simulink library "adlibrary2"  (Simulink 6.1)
undefined symbols (not defined in the file or in its folder): adlibrary2, ADM, Bit, Black, Box, d2sram_config, DDR, ddr32_config, Generation, II, Inactive, Location, Lower, SDRAM, Simulation, Subsystem, Width, xbsIndex_r3, XPL, XRC, XRM, zbt32_config, zbt64_config
libraries: xbsIndex_r3 x633
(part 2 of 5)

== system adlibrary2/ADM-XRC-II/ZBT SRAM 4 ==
  d : Inport  Port=1  LatchInput=off
  a : Inport  Port=2  LatchInput=off
  w : Inport  Port=3  LatchInput=off
  r : Inport  Port=4  LatchInput=off
  be : Inport  Port=5  LatchInput=off
  adlocb_in : Inport  Port=6  LatchInput=off
  Constant : xbsIndex_r3/Constant  const=0  equ=P=C  arith_type=Unsigned  n_bits=34  bin_pt=0  opselect=C  inp2=PCIN>>17  opr=+  inp1=P  carry=CIN  iostate=0  explicit_period=on  period=1  dbl_ovrd=off
  Convert : xbsIndex_r3/Convert  arith_type=Unsigned  n_bits=34  bin_pt=0  quantization=Truncate  overflow=Wrap  latency=0  explicit_period=on  period=1  dbl_ovrd=off  show_param=off  inserted_by_tool=off  pipeline=off
  Simulation Multiplexer : xbsIndex_r3/Simulation Multiplexer  sim_sel=1  hw_sel=2
  Simulation Multiplexer1 : xbsIndex_r3/Simulation Multiplexer  sim_sel=1  hw_sel=2
  Simulation Multiplexer2 : xbsIndex_r3/Simulation Multiplexer  sim_sel=1  hw_sel=2
  ZBT SRAM 32Bit Generation : Subsystem
  ZBT SRAM 32Bit Simulation : Subsystem
  q : Outport
  qv : Outport  Port=2
  adlocb_out : Outport  Port=3
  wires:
  Constant/1 -> Simulation Multiplexer2/1
  adlocb_in/1 -> ZBT SRAM 32Bit Generation/6(adlocb_in)
  ZBT SRAM 32Bit Generation/3(adlocb_out) -> Convert/1
  Simulation Multiplexer2/1 -> adlocb_out/1
  be/1 -> ZBT SRAM 32Bit Generation/5(be), ZBT SRAM 32Bit Simulation/5(be)
  Simulation Multiplexer/1 -> q/1
  Simulation Multiplexer1/1 -> qv/1
  ZBT SRAM 32Bit Generation/2(qv) -> Simulation Multiplexer1/2
  ZBT SRAM 32Bit Generation/1(q) -> Simulation Multiplexer/2
  ZBT SRAM 32Bit Simulation/1(q) -> Simulation Multiplexer/1
  ZBT SRAM 32Bit Simulation/2(qv) -> Simulation Multiplexer1/1
  d/1 -> ZBT SRAM 32Bit Simulation/1(d), ZBT SRAM 32Bit Generation/1(d)
  a/1 -> ZBT SRAM 32Bit Simulation/2(a), ZBT SRAM 32Bit Generation/2(a)
  w/1 -> ZBT SRAM 32Bit Simulation/3(w), ZBT SRAM 32Bit Generation/3(w)
  r/1 -> ZBT SRAM 32Bit Simulation/4(r), ZBT SRAM 32Bit Generation/4(r)
  Convert/1 -> Simulation Multiplexer2/2

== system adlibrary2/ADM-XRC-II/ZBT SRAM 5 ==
  d : Inport  Port=1  LatchInput=off
  a : Inport  Port=2  LatchInput=off
  w : Inport  Port=3  LatchInput=off
  r : Inport  Port=4  LatchInput=off
  be : Inport  Port=5  LatchInput=off
  adlocb_in : Inport  Port=6  LatchInput=off
  Constant : xbsIndex_r3/Constant  const=0  equ=P=C  arith_type=Unsigned  n_bits=34  bin_pt=0  opselect=C  inp2=PCIN>>17  opr=+  inp1=P  carry=CIN  iostate=0  explicit_period=on  period=1  dbl_ovrd=off
  Convert : xbsIndex_r3/Convert  arith_type=Unsigned  n_bits=34  bin_pt=0  quantization=Truncate  overflow=Wrap  latency=0  explicit_period=on  period=1  dbl_ovrd=off  show_param=off  inserted_by_tool=off  pipeline=off
  Simulation Multiplexer : xbsIndex_r3/Simulation Multiplexer  sim_sel=1  hw_sel=2
  Simulation Multiplexer1 : xbsIndex_r3/Simulation Multiplexer  sim_sel=1  hw_sel=2
  Simulation Multiplexer2 : xbsIndex_r3/Simulation Multiplexer  sim_sel=1  hw_sel=2
  ZBT SRAM 32Bit Generation : Subsystem
  ZBT SRAM 32Bit Simulation : Subsystem
  q : Outport
  qv : Outport  Port=2
  adlocb_out : Outport  Port=3
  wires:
  r/1 -> ZBT SRAM 32Bit Generation/4(r), ZBT SRAM 32Bit Simulation/4(r)
  w/1 -> ZBT SRAM 32Bit Generation/3(w), ZBT SRAM 32Bit Simulation/3(w)
  a/1 -> ZBT SRAM 32Bit Generation/2(a), ZBT SRAM 32Bit Simulation/2(a)
  d/1 -> ZBT SRAM 32Bit Generation/1(d), ZBT SRAM 32Bit Simulation/1(d)
  ZBT SRAM 32Bit Simulation/2(qv) -> Simulation Multiplexer1/1
  ZBT SRAM 32Bit Simulation/1(q) -> Simulation Multiplexer/1
  ZBT SRAM 32Bit Generation/1(q) -> Simulation Multiplexer/2
  ZBT SRAM 32Bit Generation/2(qv) -> Simulation Multiplexer1/2
  Simulation Multiplexer1/1 -> qv/1
  Simulation Multiplexer/1 -> q/1
  be/1 -> ZBT SRAM 32Bit Simulation/5(be), ZBT SRAM 32Bit Generation/5(be)
  Simulation Multiplexer2/1 -> adlocb_out/1
  ZBT SRAM 32Bit Generation/3(adlocb_out) -> Convert/1
  adlocb_in/1 -> ZBT SRAM 32Bit Generation/6(adlocb_in)
  Constant/1 -> Simulation Multiplexer2/1
  Convert/1 -> Simulation Multiplexer2/2

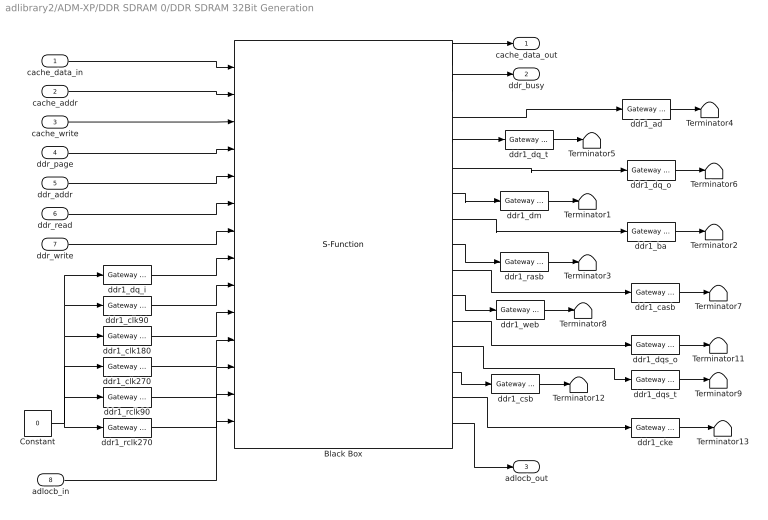
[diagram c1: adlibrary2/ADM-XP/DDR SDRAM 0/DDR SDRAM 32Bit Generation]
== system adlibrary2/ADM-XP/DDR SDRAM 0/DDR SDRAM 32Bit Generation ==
  cache_data_in : Inport  Port=1  LatchInput=off
  cache_addr : Inport  Port=2  LatchInput=off
  cache_write : Inport  Port=3  LatchInput=off
  ddr_page : Inport  Port=4  LatchInput=off
  ddr_addr : Inport  Port=5  LatchInput=off
  ddr_read : Inport  Port=6  LatchInput=off
  ddr_write : Inport  Port=7  LatchInput=off
  adlocb_in : Inport  Port=8  LatchInput=off
  Black Box : S-Function  AncestorBlock=xbsIndex_r3/Black Box  FunctionName=xlblackbox2  Parameters=sfcn_mwsv__  mask(Xilinx Blackbox Block){init_code=ddr32_config, sim_method=Inactive, engine_block=, show_param=on, xl_area=[375, 550, 2, 337, 9, 0, 0], xl_use_area=on, adlocb_devid=4, ddr_size=64}
      mask prompts: init_code "Block Configuration M-Function"; sim_method "Simulation Mode"; engine_block "HDL Co-Simulator To Use  (specify helper block by name)"; show_param "---------------------- Show Implementation Parameters -----------------------------------------------------------------------------------"; xl_area "FPGA Area [Slices, FFs, BRAMs, LUTs, IOBs, Emb. Mults, TBUFs]"; xl_use_area "Use Area Above For Estimation"; adlocb_devid "ADLOCB DEV ID"; ddr_size "DDR BANK SIZE(MB)"
      mask help: Incorporates black box HDL and simulation model into a System Generator design. You must supply a Black Box with certain information about the HDL component you would like to bring into System Generator. This information is provided through a Matlab function. When "Simulation Mode" is set to "Inactive," you will typically want to provide a separate simulation model by using a Simulation Multiplexer. When "Simulation Mode" is set to "Use HDL Co-Simulation", you must include a ModelSim block in the design.
      mask init:
      | [designRoot, family, part, speed, package, simulinkPeriod, sysclkPeriod, dbl_ovrd, trimVbit] = xlSysgenSettings(gcb,0,0);
      | 
      | [bg,fg] = xlcmap('XBlock');
      | iPos = get_param(gcb,'Position');
      | iWidth=iPos(3)-iPos(1); iHeight=iPos(4)-iPos(2);
      | iCx=iWidth/2;
      | iCy=iHeight/2;
      | [logoX, logoY] = xlogo(iPos);
      | zstr='z'; zpstr='-1';
      | zstrx = iCx-3; if (zstrx<16) zstr='';zpstr=''; end
      | zstry = iCy;
      | 
      | precision0 = 1;
      | latency = 0;
      | dblOvrd = 0;
      | 
      | mdlPath = xlGetMdlDir(bdroot);
      | 
      | refBlk = get_param(gcb,'referenceBlock');
      | if (isempty(refBlk) | strncmp(refBlk,'xbsIndex',8))
      | 	srcPath = mdlPath;
      | else
      | 	srcPath = xlPathToReference;
      | 	if (isempty(srcPath))
      | 		srcPath = mdlPath;
      | 	end
      | end
      | 
      | if (sim_method==2)
      | 	validEngineBlock = 0;
      | 	try
      | 	  engineBlock = xlBlockNameRelPath(get_param(gcb,'Parent'),engine_block);
      | 	catch
      | 	  engineBlock = '//';
      | 	end
      | 	try 
      | 	  engineWorkDir = get_param(engineBlock,'dir');
      | 	  validEngineBlock = 1;
      | 	catch
      | 	end
      | end
      | 
      | % just pass everything to s-function
      | sfcn_mwsv__ = get_param(gcb, 'MaskWSVariables');
      | 
      | plabel = xlbbPortLabelStruct(gcb,init_code,mdlPath);
  Constant : Constant  Value=0
  Terminator{1..9,11..13} (12 alike) : Terminator
  ddr1_ad : xbsIndex_r3/Gateway Out  output_type=Double  nbits=8  bin_pt=6  arith_type=Boolean  quantization=Truncate  overflow=Wrap  hdl_port=on  timing_constraint=None  locs_specified=off  LOCs={}  needs_fixed_name=off  show_param=off
  ddr1_ba : xbsIndex_r3/Gateway Out  output_type=Double  nbits=8  bin_pt=6  arith_type=Boolean  quantization=Truncate  overflow=Wrap  hdl_port=on  timing_constraint=None  locs_specified=off  LOCs={}  needs_fixed_name=off  show_param=off
  ddr1_casb : xbsIndex_r3/Gateway Out  output_type=Double  nbits=8  bin_pt=6  arith_type=Boolean  quantization=Truncate  overflow=Wrap  hdl_port=on  timing_constraint=None  locs_specified=off  LOCs={}  needs_fixed_name=off  show_param=off
  ddr1_cke : xbsIndex_r3/Gateway Out  output_type=Double  nbits=8  bin_pt=6  arith_type=Boolean  quantization=Truncate  overflow=Wrap  hdl_port=on  timing_constraint=None  locs_specified=off  LOCs={}  needs_fixed_name=off  show_param=off
  ddr1_clk180 : xbsIndex_r3/Gateway In  arith_type=Boolean  n_bits=64  bin_pt=0  quantization=Truncate  overflow=Wrap  period=1  timing_constraint=None  locs_specified=off  LOCs={}  needs_fixed_name=off  dbl_ovrd=off  show_param=off
  ddr1_clk270 : xbsIndex_r3/Gateway In  arith_type=Boolean  n_bits=64  bin_pt=0  quantization=Truncate  overflow=Wrap  period=1  timing_constraint=None  locs_specified=off  LOCs={}  needs_fixed_name=off  dbl_ovrd=off  show_param=off
  ddr1_clk90 : xbsIndex_r3/Gateway In  arith_type=Boolean  n_bits=64  bin_pt=0  quantization=Truncate  overflow=Wrap  period=1  timing_constraint=None  locs_specified=off  LOCs={}  needs_fixed_name=off  dbl_ovrd=off  show_param=off
  ddr1_csb : xbsIndex_r3/Gateway Out  output_type=Double  nbits=8  bin_pt=6  arith_type=Boolean  quantization=Truncate  overflow=Wrap  hdl_port=on  timing_constraint=None  locs_specified=off  LOCs={}  needs_fixed_name=off  show_param=off
  ddr1_dm : xbsIndex_r3/Gateway Out  output_type=Double  nbits=8  bin_pt=6  arith_type=Boolean  quantization=Truncate  overflow=Wrap  hdl_port=on  timing_constraint=None  locs_specified=off  LOCs={}  needs_fixed_name=off  show_param=off
  ddr1_dq_i : xbsIndex_r3/Gateway In  arith_type=Unsigned  n_bits=32  bin_pt=0  quantization=Truncate  overflow=Wrap  period=1  timing_constraint=None  locs_specified=off  LOCs={}  needs_fixed_name=off  dbl_ovrd=off  show_param=off
  ddr1_dq_o : xbsIndex_r3/Gateway Out  output_type=Double  nbits=8  bin_pt=6  arith_type=Boolean  quantization=Truncate  overflow=Wrap  hdl_port=on  timing_constraint=None  locs_specified=off  LOCs={}  needs_fixed_name=off  show_param=off
  ddr1_dq_t : xbsIndex_r3/Gateway Out  output_type=Double  nbits=8  bin_pt=6  arith_type=Boolean  quantization=Truncate  overflow=Wrap  hdl_port=on  timing_constraint=None  locs_specified=off  LOCs={}  needs_fixed_name=off  show_param=off
  ddr1_dqs_o : xbsIndex_r3/Gateway Out  output_type=Double  nbits=8  bin_pt=6  arith_type=Boolean  quantization=Truncate  overflow=Wrap  hdl_port=on  timing_constraint=None  locs_specified=off  LOCs={}  needs_fixed_name=off  show_param=off
  ddr1_dqs_t : xbsIndex_r3/Gateway Out  output_type=Double  nbits=8  bin_pt=6  arith_type=Boolean  quantization=Truncate  overflow=Wrap  hdl_port=on  timing_constraint=None  locs_specified=off  LOCs={}  needs_fixed_name=off  show_param=off
  ddr1_rasb : xbsIndex_r3/Gateway Out  output_type=Double  nbits=8  bin_pt=6  arith_type=Boolean  quantization=Truncate  overflow=Wrap  hdl_port=on  timing_constraint=None  locs_specified=off  LOCs={}  needs_fixed_name=off  show_param=off
  ddr1_rclk270 : xbsIndex_r3/Gateway In  arith_type=Boolean  n_bits=64  bin_pt=0  quantization=Truncate  overflow=Wrap  period=1  timing_constraint=None  locs_specified=off  LOCs={}  needs_fixed_name=off  dbl_ovrd=off  show_param=off
  ddr1_rclk90 : xbsIndex_r3/Gateway In  arith_type=Boolean  n_bits=64  bin_pt=0  quantization=Truncate  overflow=Wrap  period=1  timing_constraint=None  locs_specified=off  LOCs={}  needs_fixed_name=off  dbl_ovrd=off  show_param=off
  ddr1_web : xbsIndex_r3/Gateway Out  output_type=Double  nbits=8  bin_pt=6  arith_type=Boolean  quantization=Truncate  overflow=Wrap  hdl_port=on  timing_constraint=None  locs_specified=off  LOCs={}  needs_fixed_name=off  show_param=off
  cache_data_out : Outport
  ddr_busy : Outport  Port=2
  adlocb_out : Outport  Port=3
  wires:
  ddr1_cke/1 -> Terminator13/1
  ddr1_csb/1 -> Terminator12/1
  ddr1_dqs_o/1 -> Terminator11/1
  ddr1_web/1 -> Terminator8/1
  ddr1_casb/1 -> Terminator7/1
  ddr1_rasb/1 -> Terminator3/1
  ddr1_ba/1 -> Terminator2/1
  ddr1_dm/1 -> Terminator1/1
  ddr1_dq_o/1 -> Terminator6/1
  ddr1_dq_t/1 -> Terminator5/1
  ddr1_ad/1 -> Terminator4/1
  Black Box/2 -> ddr_busy/1
  Black Box/1 -> cache_data_out/1
  ddr_write/1 -> Black Box/7
  ddr_read/1 -> Black Box/6
  ddr_addr/1 -> Black Box/5
  ddr_page/1 -> Black Box/4
  cache_write/1 -> Black Box/3
  cache_addr/1 -> Black Box/2
  cache_data_in/1 -> Black Box/1
  ddr1_dq_i/1 -> Black Box/8
  Constant/1 -> ddr1_dq_i/1, ddr1_clk90/1, ddr1_clk180/1, ddr1_rclk270/1, ddr1_clk270/1, ddr1_rclk90/1
  ddr1_clk90/1 -> Black Box/9
  ddr1_clk180/1 -> Black Box/10
  ddr1_clk270/1 -> Black Box/11
  ddr1_rclk90/1 -> Black Box/12
  ddr1_rclk270/1 -> Black Box/13
  ddr1_dqs_t/1 -> Terminator9/1
  Black Box/3 -> ddr1_ad/1
  Black Box/4 -> ddr1_dq_t/1
  Black Box/5 -> ddr1_dq_o/1
  Black Box/6 -> ddr1_dm/1
  Black Box/7 -> ddr1_ba/1
  Black Box/8 -> ddr1_rasb/1
  Black Box/9 -> ddr1_casb/1
  Black Box/10 -> ddr1_web/1
  Black Box/11 -> ddr1_dqs_o/1
  Black Box/12 -> ddr1_dqs_t/1
  Black Box/13 -> ddr1_csb/1
  Black Box/14 -> ddr1_cke/1
  adlocb_in/1 -> Black Box/14
  Black Box/15 -> adlocb_out/1

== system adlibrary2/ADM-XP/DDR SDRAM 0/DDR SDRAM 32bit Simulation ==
  cache_data_in : Inport  Port=1  LatchInput=off
  cache_addr : Inport  Port=2  LatchInput=off
  cache_write : Inport  Port=3  LatchInput=off
  ddr_page : Inport  Port=4  LatchInput=off
  ddr_addr : Inport  Port=5  LatchInput=off
  ddr_read : Inport  Port=6  LatchInput=off
  ddr_write : Inport  Port=7  LatchInput=off
  Disregard Subsystem : xbsIndex_r3/Disregard Subsystem  Tag=discardX
  S-Function : S-Function  FunctionName=ddr32  Parameters=memsize,0
  Subsystem : Subsystem  AncestorBlock=adlibrary2/ADM-XRC-II/XRM DDR SDRAM /DDR SDRAM 64bit Simulation/Subsystem
  Terminator13 : Terminator
  gi{0..6} (7 alike) : xbsIndex_r3/Gateway Out  output_type=Double  nbits=8  bin_pt=6  arith_type=Boolean  quantization=Truncate  overflow=Wrap  hdl_port=off  timing_constraint=None  locs_specified=off  LOCs={}  needs_fixed_name=off  show_param=off
  cache_data_out : Outport
  ddr_busy : Outport  Port=2
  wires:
  cache_data_in/1 -> gi0/1
  cache_addr/1 -> gi1/1
  cache_write/1 -> gi2/1
  ddr_page/1 -> gi3/1
  ddr_addr/1 -> gi4/1
  ddr_read/1 -> gi5/1
  ddr_write/1 -> gi6/1
  gi0/1 -> S-Function/1
  gi1/1 -> S-Function/2
  gi2/1 -> S-Function/3
  gi3/1 -> S-Function/4
  gi4/1 -> S-Function/5
  gi5/1 -> S-Function/6
  gi6/1 -> S-Function/7
  S-Function/2 -> Subsystem/2(In2)
  S-Function/1 -> Subsystem/1(In1)
  Subsystem/1(Out1) -> cache_data_out/1
  Subsystem/2(Out2) -> ddr_busy/1
  S-Function/3 -> Terminator13/1

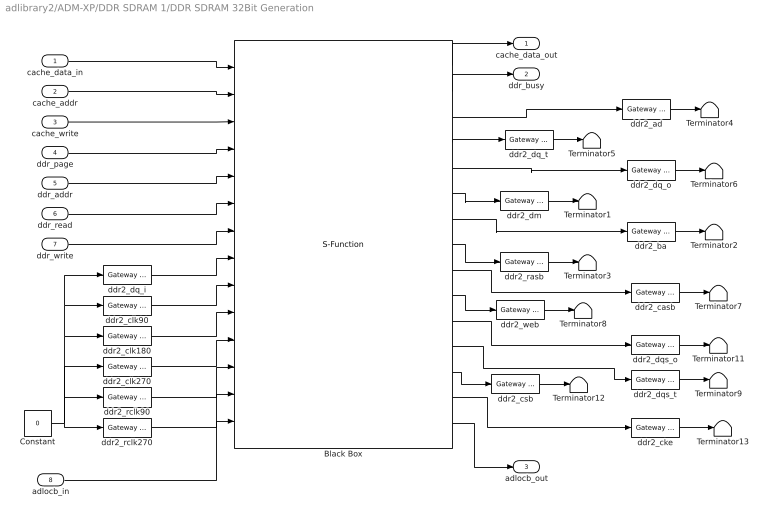
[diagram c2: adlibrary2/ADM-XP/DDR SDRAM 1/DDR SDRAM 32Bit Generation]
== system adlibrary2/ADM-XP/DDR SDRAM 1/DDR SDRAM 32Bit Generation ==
  cache_data_in : Inport  Port=1  LatchInput=off
  cache_addr : Inport  Port=2  LatchInput=off
  cache_write : Inport  Port=3  LatchInput=off
  ddr_page : Inport  Port=4  LatchInput=off
  ddr_addr : Inport  Port=5  LatchInput=off
  ddr_read : Inport  Port=6  LatchInput=off
  ddr_write : Inport  Port=7  LatchInput=off
  adlocb_in : Inport  Port=8  LatchInput=off
  Black Box : S-Function  AncestorBlock=xbsIndex_r3/Black Box  FunctionName=xlblackbox2  Parameters=sfcn_mwsv__  mask(Xilinx Blackbox Block){init_code=ddr32_config, sim_method=Inactive, engine_block=, show_param=on, xl_area=[375, 550, 2, 337, 9, 0, 0], xl_use_area=on, adlocb_devid=5, ddr_size=64}
      mask prompts: init_code "Block Configuration M-Function"; sim_method "Simulation Mode"; engine_block "HDL Co-Simulator To Use  (specify helper block by name)"; show_param "---------------------- Show Implementation Parameters -----------------------------------------------------------------------------------"; xl_area "FPGA Area [Slices, FFs, BRAMs, LUTs, IOBs, Emb. Mults, TBUFs]"; xl_use_area "Use Area Above For Estimation"; adlocb_devid "ADLOCB DEV ID"; ddr_size "DDR BANK SIZE(MB)"
      mask help: Incorporates black box HDL and simulation model into a System Generator design. You must supply a Black Box with certain information about the HDL component you would like to bring into System Generator. This information is provided through a Matlab function. When "Simulation Mode" is set to "Inactive," you will typically want to provide a separate simulation model by using a Simulation Multiplexer. When "Simulation Mode" is set to "Use HDL Co-Simulation", you must include a ModelSim block in the design.
      mask init:
      | [designRoot, family, part, speed, package, simulinkPeriod, sysclkPeriod, dbl_ovrd, trimVbit] = xlSysgenSettings(gcb,0,0);
      | 
      | [bg,fg] = xlcmap('XBlock');
      | iPos = get_param(gcb,'Position');
      | iWidth=iPos(3)-iPos(1); iHeight=iPos(4)-iPos(2);
      | iCx=iWidth/2;
      | iCy=iHeight/2;
      | [logoX, logoY] = xlogo(iPos);
      | zstr='z'; zpstr='-1';
      | zstrx = iCx-3; if (zstrx<16) zstr='';zpstr=''; end
      | zstry = iCy;
      | 
      | precision0 = 1;
      | latency = 0;
      | dblOvrd = 0;
      | 
      | mdlPath = xlGetMdlDir(bdroot);
      | 
      | refBlk = get_param(gcb,'referenceBlock');
      | if (isempty(refBlk) | strncmp(refBlk,'xbsIndex',8))
      | 	srcPath = mdlPath;
      | else
      | 	srcPath = xlPathToReference;
      | 	if (isempty(srcPath))
      | 		srcPath = mdlPath;
      | 	end
      | end
      | 
      | if (sim_method==2)
      | 	validEngineBlock = 0;
      | 	try
      | 	  engineBlock = xlBlockNameRelPath(get_param(gcb,'Parent'),engine_block);
      | 	catch
      | 	  engineBlock = '//';
      | 	end
      | 	try 
      | 	  engineWorkDir = get_param(engineBlock,'dir');
      | 	  validEngineBlock = 1;
      | 	catch
      | 	end
      | end
      | 
      | % just pass everything to s-function
      | sfcn_mwsv__ = get_param(gcb, 'MaskWSVariables');
      | 
      | plabel = xlbbPortLabelStruct(gcb,init_code,mdlPath);
  Constant : Constant  Value=0
  Terminator{1..9,11..13} (12 alike) : Terminator
  ddr2_ad : xbsIndex_r3/Gateway Out  output_type=Double  nbits=8  bin_pt=6  arith_type=Boolean  quantization=Truncate  overflow=Wrap  hdl_port=on  timing_constraint=None  locs_specified=off  LOCs={}  needs_fixed_name=off  show_param=off
  ddr2_ba : xbsIndex_r3/Gateway Out  output_type=Double  nbits=8  bin_pt=6  arith_type=Boolean  quantization=Truncate  overflow=Wrap  hdl_port=on  timing_constraint=None  locs_specified=off  LOCs={}  needs_fixed_name=off  show_param=off
  ddr2_casb : xbsIndex_r3/Gateway Out  output_type=Double  nbits=8  bin_pt=6  arith_type=Boolean  quantization=Truncate  overflow=Wrap  hdl_port=on  timing_constraint=None  locs_specified=off  LOCs={}  needs_fixed_name=off  show_param=off
  ddr2_cke : xbsIndex_r3/Gateway Out  output_type=Double  nbits=8  bin_pt=6  arith_type=Boolean  quantization=Truncate  overflow=Wrap  hdl_port=on  timing_constraint=None  locs_specified=off  LOCs={}  needs_fixed_name=off  show_param=off
  ddr2_clk180 : xbsIndex_r3/Gateway In  arith_type=Boolean  n_bits=64  bin_pt=0  quantization=Truncate  overflow=Wrap  period=1  timing_constraint=None  locs_specified=off  LOCs={}  needs_fixed_name=off  dbl_ovrd=off  show_param=off
  ddr2_clk270 : xbsIndex_r3/Gateway In  arith_type=Boolean  n_bits=64  bin_pt=0  quantization=Truncate  overflow=Wrap  period=1  timing_constraint=None  locs_specified=off  LOCs={}  needs_fixed_name=off  dbl_ovrd=off  show_param=off
  ddr2_clk90 : xbsIndex_r3/Gateway In  arith_type=Boolean  n_bits=64  bin_pt=0  quantization=Truncate  overflow=Wrap  period=1  timing_constraint=None  locs_specified=off  LOCs={}  needs_fixed_name=off  dbl_ovrd=off  show_param=off
  ddr2_csb : xbsIndex_r3/Gateway Out  output_type=Double  nbits=8  bin_pt=6  arith_type=Boolean  quantization=Truncate  overflow=Wrap  hdl_port=on  timing_constraint=None  locs_specified=off  LOCs={}  needs_fixed_name=off  show_param=off
  ddr2_dm : xbsIndex_r3/Gateway Out  output_type=Double  nbits=8  bin_pt=6  arith_type=Boolean  quantization=Truncate  overflow=Wrap  hdl_port=on  timing_constraint=None  locs_specified=off  LOCs={}  needs_fixed_name=off  show_param=off
  ddr2_dq_i : xbsIndex_r3/Gateway In  arith_type=Unsigned  n_bits=32  bin_pt=0  quantization=Truncate  overflow=Wrap  period=1  timing_constraint=None  locs_specified=off  LOCs={}  needs_fixed_name=off  dbl_ovrd=off  show_param=off
  ddr2_dq_o : xbsIndex_r3/Gateway Out  output_type=Double  nbits=8  bin_pt=6  arith_type=Boolean  quantization=Truncate  overflow=Wrap  hdl_port=on  timing_constraint=None  locs_specified=off  LOCs={}  needs_fixed_name=off  show_param=off
  ddr2_dq_t : xbsIndex_r3/Gateway Out  output_type=Double  nbits=8  bin_pt=6  arith_type=Boolean  quantization=Truncate  overflow=Wrap  hdl_port=on  timing_constraint=None  locs_specified=off  LOCs={}  needs_fixed_name=off  show_param=off
  ddr2_dqs_o : xbsIndex_r3/Gateway Out  output_type=Double  nbits=8  bin_pt=6  arith_type=Boolean  quantization=Truncate  overflow=Wrap  hdl_port=on  timing_constraint=None  locs_specified=off  LOCs={}  needs_fixed_name=off  show_param=off
  ddr2_dqs_t : xbsIndex_r3/Gateway Out  output_type=Double  nbits=8  bin_pt=6  arith_type=Boolean  quantization=Truncate  overflow=Wrap  hdl_port=on  timing_constraint=None  locs_specified=off  LOCs={}  needs_fixed_name=off  show_param=off
  ddr2_rasb : xbsIndex_r3/Gateway Out  output_type=Double  nbits=8  bin_pt=6  arith_type=Boolean  quantization=Truncate  overflow=Wrap  hdl_port=on  timing_constraint=None  locs_specified=off  LOCs={}  needs_fixed_name=off  show_param=off
  ddr2_rclk270 : xbsIndex_r3/Gateway In  arith_type=Boolean  n_bits=64  bin_pt=0  quantization=Truncate  overflow=Wrap  period=1  timing_constraint=None  locs_specified=off  LOCs={}  needs_fixed_name=off  dbl_ovrd=off  show_param=off
  ddr2_rclk90 : xbsIndex_r3/Gateway In  arith_type=Boolean  n_bits=64  bin_pt=0  quantization=Truncate  overflow=Wrap  period=1  timing_constraint=None  locs_specified=off  LOCs={}  needs_fixed_name=off  dbl_ovrd=off  show_param=off
  ddr2_web : xbsIndex_r3/Gateway Out  output_type=Double  nbits=8  bin_pt=6  arith_type=Boolean  quantization=Truncate  overflow=Wrap  hdl_port=on  timing_constraint=None  locs_specified=off  LOCs={}  needs_fixed_name=off  show_param=off
  cache_data_out : Outport
  ddr_busy : Outport  Port=2
  adlocb_out : Outport  Port=3
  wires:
  Black Box/15 -> adlocb_out/1
  adlocb_in/1 -> Black Box/14
  Black Box/14 -> ddr2_cke/1
  Black Box/13 -> ddr2_csb/1
  Black Box/12 -> ddr2_dqs_t/1
  Black Box/11 -> ddr2_dqs_o/1
  Black Box/10 -> ddr2_web/1
  Black Box/9 -> ddr2_casb/1
  Black Box/8 -> ddr2_rasb/1
  Black Box/7 -> ddr2_ba/1
  Black Box/6 -> ddr2_dm/1
  Black Box/5 -> ddr2_dq_o/1
  Black Box/4 -> ddr2_dq_t/1
  Black Box/3 -> ddr2_ad/1
  ddr2_dqs_t/1 -> Terminator9/1
  ddr2_rclk270/1 -> Black Box/13
  ddr2_rclk90/1 -> Black Box/12
  ddr2_clk270/1 -> Black Box/11
  ddr2_clk180/1 -> Black Box/10
  ddr2_clk90/1 -> Black Box/9
  Constant/1 -> ddr2_rclk90/1, ddr2_clk270/1, ddr2_rclk270/1, ddr2_clk180/1, ddr2_clk90/1, ddr2_dq_i/1
  ddr2_dq_i/1 -> Black Box/8
  cache_data_in/1 -> Black Box/1
  cache_addr/1 -> Black Box/2
  cache_write/1 -> Black Box/3
  ddr_page/1 -> Black Box/4
  ddr_addr/1 -> Black Box/5
  ddr_read/1 -> Black Box/6
  ddr_write/1 -> Black Box/7
  Black Box/1 -> cache_data_out/1
  Black Box/2 -> ddr_busy/1
  ddr2_ad/1 -> Terminator4/1
  ddr2_dq_t/1 -> Terminator5/1
  ddr2_dq_o/1 -> Terminator6/1
  ddr2_dm/1 -> Terminator1/1
  ddr2_ba/1 -> Terminator2/1
  ddr2_rasb/1 -> Terminator3/1
  ddr2_casb/1 -> Terminator7/1
  ddr2_web/1 -> Terminator8/1
  ddr2_dqs_o/1 -> Terminator11/1
  ddr2_csb/1 -> Terminator12/1
  ddr2_cke/1 -> Terminator13/1

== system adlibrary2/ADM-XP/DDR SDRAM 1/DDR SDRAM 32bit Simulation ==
  cache_data_in : Inport  Port=1  LatchInput=off
  cache_addr : Inport  Port=2  LatchInput=off
  cache_write : Inport  Port=3  LatchInput=off
  ddr_page : Inport  Port=4  LatchInput=off
  ddr_addr : Inport  Port=5  LatchInput=off
  ddr_read : Inport  Port=6  LatchInput=off
  ddr_write : Inport  Port=7  LatchInput=off
  Disregard Subsystem : xbsIndex_r3/Disregard Subsystem  Tag=discardX
  S-Function : S-Function  FunctionName=ddr32  Parameters=memsize,1
  Subsystem : Subsystem  AncestorBlock=adlibrary2/ADM-XRC-II/XRM DDR SDRAM /DDR SDRAM 64bit Simulation/Subsystem
  Terminator13 : Terminator
  gi{0..6} (7 alike) : xbsIndex_r3/Gateway Out  output_type=Double  nbits=8  bin_pt=6  arith_type=Boolean  quantization=Truncate  overflow=Wrap  hdl_port=off  timing_constraint=None  locs_specified=off  LOCs={}  needs_fixed_name=off  show_param=off
  cache_data_out : Outport
  ddr_busy : Outport  Port=2
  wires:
  S-Function/3 -> Terminator13/1
  Subsystem/2(Out2) -> ddr_busy/1
  Subsystem/1(Out1) -> cache_data_out/1
  S-Function/1 -> Subsystem/1(In1)
  S-Function/2 -> Subsystem/2(In2)
  gi6/1 -> S-Function/7
  gi5/1 -> S-Function/6
  gi4/1 -> S-Function/5
  gi3/1 -> S-Function/4
  gi2/1 -> S-Function/3
  gi1/1 -> S-Function/2
  gi0/1 -> S-Function/1
  ddr_write/1 -> gi6/1
  ddr_read/1 -> gi5/1
  ddr_addr/1 -> gi4/1
  ddr_page/1 -> gi3/1
  cache_write/1 -> gi2/1
  cache_addr/1 -> gi1/1
  cache_data_in/1 -> gi0/1

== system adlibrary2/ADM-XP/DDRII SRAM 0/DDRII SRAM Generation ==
  d : Inport  Port=1  LatchInput=off
  a : Inport  Port=2  LatchInput=off
  w : Inport  Port=3  LatchInput=off
  r : Inport  Port=4  LatchInput=off
  be : Inport  Port=5  LatchInput=off
  adlocb_in : Inport  Port=6  LatchInput=off
  Black Box : S-Function  FunctionName=xlblackbox2  Parameters=sfcn_mwsv__  mask(Xilinx Blackbox Block){init_code=d2sram_config, sim_method=Inactive, engine_block=, show_param=off, xl_area=[0, 0, 0, 0, 0, 0, 0], xl_use_area=off, adlocb_devid=0}
      mask prompts: init_code "Block Configuration M-Function"; sim_method "Simulation Mode"; engine_block "HDL Co-Simulator To Use  (specify helper block by name)"; show_param "---------------------- Show Implementation Parameters -----------------------------------------------------------------------------------"; xl_area "FPGA Area [Slices, FFs, BRAMs, LUTs, IOBs, Emb. Mults, TBUFs]"; xl_use_area "Use Area Above For Estimation"; adlocb_devid "ADLOCB DEV ID"
      mask help: Incorporates black box HDL and simulation model into a System Generator design. You must supply a Black Box with certain information about the HDL component you would like to bring into System Generator. This information is provided through a Matlab function. When "Simulation Mode" is set to "Inactive," you will typically want to provide a separate simulation model by using a Simulation Multiplexer. When "Simulation Mode" is set to "Use HDL Co-Simulation", you must include a ModelSim block in the design.
      mask init:
      | [designRoot, family, part, speed, package, simulinkPeriod, sysclkPeriod, dbl_ovrd, trimVbit] = xlSysgenSettings(gcb,0,0);
      | 
      | [bg,fg] = xlcmap('XBlock');
      | iPos = get_param(gcb,'Position');
      | iWidth=iPos(3)-iPos(1); iHeight=iPos(4)-iPos(2);
      | iCx=iWidth/2;
      | iCy=iHeight/2;
      | [logoX, logoY] = xlogo(iPos);
      | zstr='z'; zpstr='-1';
      | zstrx = iCx-3; if (zstrx<16) zstr='';zpstr=''; end
      | zstry = iCy;
      | 
      | precision0 = 1;
      | latency = 0;
      | dblOvrd = 0;
      | 
      | mdlPath = xlGetMdlDir(bdroot);
      | 
      | refBlk = get_param(gcb,'referenceBlock');
      | if (isempty(refBlk) | strncmp(refBlk,'xbsIndex',8))
      | 	srcPath = mdlPath;
      | else
      | 	srcPath = xlPathToReference;
      | 	if (isempty(srcPath))
      | 		srcPath = mdlPath;
      | 	end
      | end
      | 
      | if (sim_method==2)
      | 	validEngineBlock = 0;
      | 	try
      | 	  engineBlock = xlBlockNameRelPath(get_param(gcb,'Parent'),engine_block);
      | 	catch
      | 	  engineBlock = '//';
      | 	end
      | 	try 
      | 	  engineWorkDir = get_param(engineBlock,'dir');
      | 	  validEngineBlock = 1;
      | 	catch
      | 	end
      | end
      | 
      | % just pass everything to s-function
      | sfcn_mwsv__ = get_param(gcb, 'MaskWSVariables');
      | 
      | plabel = xlbbPortLabelStruct(gcb,init_code,mdlPath);
  Constant : Constant  Value=0
  Convert : xbsIndex_r3/Convert  arith_type=Unsigned  n_bits=66  bin_pt=0  quantization=Truncate  overflow=Wrap  latency=0  explicit_period=on  period=1  dbl_ovrd=off  show_param=off  inserted_by_tool=off  pipeline=off
  Terminator{,1..3} (4 alike) : Terminator
  r0_clk180 : xbsIndex_r3/Gateway In  arith_type=Boolean  n_bits=1  bin_pt=0  quantization=Truncate  overflow=Wrap  period=1  timing_constraint=None  locs_specified=off  LOCs={}  needs_fixed_name=off  dbl_ovrd=off  show_param=off
  r0_clk270 : xbsIndex_r3/Gateway In  arith_type=Boolean  n_bits=1  bin_pt=0  quantization=Truncate  overflow=Wrap  period=1  timing_constraint=None  locs_specified=off  LOCs={}  needs_fixed_name=off  dbl_ovrd=off  show_param=off
  r0_clk90 : xbsIndex_r3/Gateway In  arith_type=Boolean  n_bits=1  bin_pt=0  quantization=Truncate  overflow=Wrap  period=1  timing_constraint=None  locs_specified=off  LOCs={}  needs_fixed_name=off  dbl_ovrd=off  show_param=off
  r0_rst : xbsIndex_r3/Gateway In  arith_type=Boolean  n_bits=1  bin_pt=0  quantization=Truncate  overflow=Wrap  period=1  timing_constraint=None  locs_specified=off  LOCs={}  needs_fixed_name=off  dbl_ovrd=off  show_param=off
  ra0 : xbsIndex_r3/Gateway Out  output_type=Double  nbits=8  bin_pt=6  arith_type=Boolean  quantization=Truncate  overflow=Wrap  hdl_port=on  timing_constraint=None  locs_specified=off  LOCs={}  needs_fixed_name=off  show_param=off
  rc0 : xbsIndex_r3/Gateway Out  output_type=Double  nbits=8  bin_pt=6  arith_type=Boolean  quantization=Truncate  overflow=Wrap  hdl_port=on  timing_constraint=None  locs_specified=off  LOCs={}  needs_fixed_name=off  show_param=off
  rd0_i : xbsIndex_r3/Gateway In  arith_type=Unsigned  n_bits=32  bin_pt=0  quantization=Truncate  overflow=Wrap  period=1  timing_constraint=None  locs_specified=off  LOCs={}  needs_fixed_name=off  dbl_ovrd=off  show_param=off
  rd0_o : xbsIndex_r3/Gateway Out  output_type=Double  nbits=8  bin_pt=6  arith_type=Boolean  quantization=Truncate  overflow=Wrap  hdl_port=on  timing_constraint=None  locs_specified=off  LOCs={}  needs_fixed_name=off  show_param=off
  rd0_t : xbsIndex_r3/Gateway Out  output_type=Double  nbits=8  bin_pt=6  arith_type=Boolean  quantization=Truncate  overflow=Wrap  hdl_port=on  timing_constraint=None  locs_specified=off  LOCs={}  needs_fixed_name=off  show_param=off
  q : Outport
  qv : Outport  Port=2
  adlocb_out : Outport  Port=3
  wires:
  rc0/1 -> Terminator3/1
  ra0/1 -> Terminator2/1
  rd0_t/1 -> Terminator1/1
  rd0_o/1 -> Terminator/1
  Constant/1 -> rd0_i/1, r0_rst/1, r0_clk270/1, r0_clk180/1, r0_clk90/1
  be/1 -> Black Box/7
  d/1 -> Black Box/6
  a/1 -> Black Box/5
  w/1 -> Black Box/9
  r/1 -> Black Box/8
  Black Box/4 -> rd0_t/1
  Black Box/3 -> rd0_o/1
  Black Box/2 -> rc0/1
  Black Box/1 -> ra0/1
  Black Box/5 -> q/1
  r0_rst/1 -> Black Box/10
  r0_clk270/1 -> Black Box/4
  r0_clk180/1 -> Black Box/3
  r0_clk90/1 -> Black Box/2
  rd0_i/1 -> Black Box/1
  Black Box/6 -> qv/1
  Convert/1 -> adlocb_out/1
  adlocb_in/1 -> Black Box/11
  Black Box/7 -> Convert/1

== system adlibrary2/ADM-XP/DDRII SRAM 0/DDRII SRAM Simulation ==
  d : Inport  Port=1  LatchInput=off
  a : Inport  Port=2  LatchInput=off
  w : Inport  Port=3  LatchInput=off
  r : Inport  Port=4  LatchInput=off
  be : Inport  Port=5  LatchInput=off
  Concat : xbsIndex_r3/Concat  num_inputs=2  explicit_period=off  period=1  dbl_ovrd=off
  Disregard Subsystem : xbsIndex_r3/Disregard Subsystem  Tag=discardX
  Gateway In1 : xbsIndex_r3/Gateway In  arith_type=Unsigned  n_bits=32  bin_pt=0  quantization=Truncate  overflow=Wrap  period=1  timing_constraint=None  locs_specified=off  LOCs={}  needs_fixed_name=off  dbl_ovrd=on  show_param=off
  Gateway In6 : xbsIndex_r3/Gateway In  arith_type=Boolean  n_bits=1  bin_pt=0  quantization=Truncate  overflow=Wrap  period=1  timing_constraint=None  locs_specified=off  LOCs={}  needs_fixed_name=off  dbl_ovrd=on  show_param=off
  Gateway In7 : xbsIndex_r3/Gateway In  arith_type=Unsigned  n_bits=32  bin_pt=0  quantization=Truncate  overflow=Wrap  period=1  timing_constraint=None  locs_specified=off  LOCs={}  needs_fixed_name=off  dbl_ovrd=on  show_param=off
  Gateway Out{,1..5} (6 alike) : xbsIndex_r3/Gateway Out  output_type=Double  nbits=8  bin_pt=6  arith_type=Boolean  quantization=Truncate  overflow=Wrap  hdl_port=off  timing_constraint=None  locs_specified=off  LOCs={}  needs_fixed_name=off  show_param=off
  S-Function : S-Function  FunctionName=d2sram  Parameters=0
  Slice : xbsIndex_r3/Slice  mode=Lower Bit Location + Width  nbits=32  bit1=0  base1=MSB of Input  bit0=0  base0=LSB of Input  boolean_output=off  explicit_period=off  period=1  dbl_ovrd=off
  Slice1 : xbsIndex_r3/Slice  mode=Lower Bit Location + Width  nbits=32  bit1=0  base1=MSB of Input  bit0=32  base0=LSB of Input  boolean_output=off  explicit_period=off  period=1  dbl_ovrd=off
  q : Outport
  qv : Outport  Port=2
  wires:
  Concat/1 -> q/1
  Gateway In1/1 -> Concat/2
  Gateway In7/1 -> Concat/1
  d/1 -> Slice/1, Slice1/1
  Slice/1 -> Gateway Out1/1
  Slice1/1 -> Gateway Out/1
  Gateway Out5/1 -> S-Function/6
  be/1 -> Gateway Out5/1
  S-Function/3 -> Gateway In6/1
  Gateway In6/1 -> qv/1
  S-Function/2 -> Gateway In1/1
  Gateway Out4/1 -> S-Function/5
  r/1 -> Gateway Out4/1
  Gateway Out3/1 -> S-Function/4
  Gateway Out2/1 -> S-Function/3
  Gateway Out1/1 -> S-Function/2
  Gateway Out/1 -> S-Function/1
  S-Function/1 -> Gateway In7/1
  w/1 -> Gateway Out3/1
  a/1 -> Gateway Out2/1

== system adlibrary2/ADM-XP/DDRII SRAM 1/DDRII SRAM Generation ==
  d : Inport  Port=1  LatchInput=off
  a : Inport  Port=2  LatchInput=off
  w : Inport  Port=3  LatchInput=off
  r : Inport  Port=4  LatchInput=off
  be : Inport  Port=5  LatchInput=off
  adlocb_in : Inport  Port=6  LatchInput=off
  Black Box : S-Function  FunctionName=xlblackbox2  Parameters=sfcn_mwsv__  mask(Xilinx Blackbox Block){init_code=d2sram_config, sim_method=Inactive, engine_block=, show_param=off, xl_area=[0, 0, 0, 0, 0, 0, 0], xl_use_area=off, adlocb_devid=1}
      mask prompts: init_code "Block Configuration M-Function"; sim_method "Simulation Mode"; engine_block "HDL Co-Simulator To Use  (specify helper block by name)"; show_param "---------------------- Show Implementation Parameters -----------------------------------------------------------------------------------"; xl_area "FPGA Area [Slices, FFs, BRAMs, LUTs, IOBs, Emb. Mults, TBUFs]"; xl_use_area "Use Area Above For Estimation"; adlocb_devid "ADLOCB DEV ID"
      mask help: Incorporates black box HDL and simulation model into a System Generator design. You must supply a Black Box with certain information about the HDL component you would like to bring into System Generator. This information is provided through a Matlab function. When "Simulation Mode" is set to "Inactive," you will typically want to provide a separate simulation model by using a Simulation Multiplexer. When "Simulation Mode" is set to "Use HDL Co-Simulation", you must include a ModelSim block in the design.
      mask init:
      | [designRoot, family, part, speed, package, simulinkPeriod, sysclkPeriod, dbl_ovrd, trimVbit] = xlSysgenSettings(gcb,0,0);
      | 
      | [bg,fg] = xlcmap('XBlock');
      | iPos = get_param(gcb,'Position');
      | iWidth=iPos(3)-iPos(1); iHeight=iPos(4)-iPos(2);
      | iCx=iWidth/2;
      | iCy=iHeight/2;
      | [logoX, logoY] = xlogo(iPos);
      | zstr='z'; zpstr='-1';
      | zstrx = iCx-3; if (zstrx<16) zstr='';zpstr=''; end
      | zstry = iCy;
      | 
      | precision0 = 1;
      | latency = 0;
      | dblOvrd = 0;
      | 
      | mdlPath = xlGetMdlDir(bdroot);
      | 
      | refBlk = get_param(gcb,'referenceBlock');
      | if (isempty(refBlk) | strncmp(refBlk,'xbsIndex',8))
      | 	srcPath = mdlPath;
      | else
      | 	srcPath = xlPathToReference;
      | 	if (isempty(srcPath))
      | 		srcPath = mdlPath;
      | 	end
      | end
      | 
      | if (sim_method==2)
      | 	validEngineBlock = 0;
      | 	try
      | 	  engineBlock = xlBlockNameRelPath(get_param(gcb,'Parent'),engine_block);
      | 	catch
      | 	  engineBlock = '//';
      | 	end
      | 	try 
      | 	  engineWorkDir = get_param(engineBlock,'dir');
      | 	  validEngineBlock = 1;
      | 	catch
      | 	end
      | end
      | 
      | % just pass everything to s-function
      | sfcn_mwsv__ = get_param(gcb, 'MaskWSVariables');
      | 
      | plabel = xlbbPortLabelStruct(gcb,init_code,mdlPath);
  Constant : Constant  Value=0
  Convert : xbsIndex_r3/Convert  arith_type=Unsigned  n_bits=66  bin_pt=0  quantization=Truncate  overflow=Wrap  latency=0  explicit_period=on  period=1  dbl_ovrd=off  show_param=off  inserted_by_tool=off  pipeline=off
  Terminator{,1..3} (4 alike) : Terminator
  r1_clk180 : xbsIndex_r3/Gateway In  arith_type=Boolean  n_bits=1  bin_pt=0  quantization=Truncate  overflow=Wrap  period=1  timing_constraint=None  locs_specified=off  LOCs={}  needs_fixed_name=off  dbl_ovrd=off  show_param=off
  r1_clk270 : xbsIndex_r3/Gateway In  arith_type=Boolean  n_bits=1  bin_pt=0  quantization=Truncate  overflow=Wrap  period=1  timing_constraint=None  locs_specified=off  LOCs={}  needs_fixed_name=off  dbl_ovrd=off  show_param=off
  r1_clk90 : xbsIndex_r3/Gateway In  arith_type=Boolean  n_bits=1  bin_pt=0  quantization=Truncate  overflow=Wrap  period=1  timing_constraint=None  locs_specified=off  LOCs={}  needs_fixed_name=off  dbl_ovrd=off  show_param=off
  r1_rst : xbsIndex_r3/Gateway In  arith_type=Boolean  n_bits=1  bin_pt=0  quantization=Truncate  overflow=Wrap  period=1  timing_constraint=None  locs_specified=off  LOCs={}  needs_fixed_name=off  dbl_ovrd=off  show_param=off
  ra1 : xbsIndex_r3/Gateway Out  output_type=Double  nbits=8  bin_pt=6  arith_type=Boolean  quantization=Truncate  overflow=Wrap  hdl_port=on  timing_constraint=None  locs_specified=off  LOCs={}  needs_fixed_name=off  show_param=off
  rc1 : xbsIndex_r3/Gateway Out  output_type=Double  nbits=8  bin_pt=6  arith_type=Boolean  quantization=Truncate  overflow=Wrap  hdl_port=on  timing_constraint=None  locs_specified=off  LOCs={}  needs_fixed_name=off  show_param=off
  rd1_i : xbsIndex_r3/Gateway In  arith_type=Unsigned  n_bits=32  bin_pt=0  quantization=Truncate  overflow=Wrap  period=1  timing_constraint=None  locs_specified=off  LOCs={}  needs_fixed_name=off  dbl_ovrd=off  show_param=off
  rd1_o : xbsIndex_r3/Gateway Out  output_type=Double  nbits=8  bin_pt=6  arith_type=Boolean  quantization=Truncate  overflow=Wrap  hdl_port=on  timing_constraint=None  locs_specified=off  LOCs={}  needs_fixed_name=off  show_param=off
  rd1_t : xbsIndex_r3/Gateway Out  output_type=Double  nbits=8  bin_pt=6  arith_type=Boolean  quantization=Truncate  overflow=Wrap  hdl_port=on  timing_constraint=None  locs_specified=off  LOCs={}  needs_fixed_name=off  show_param=off
  q : Outport
  qv : Outport  Port=2
  adlocb_out : Outport  Port=3
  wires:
  Black Box/7 -> Convert/1
  adlocb_in/1 -> Black Box/11
  Convert/1 -> adlocb_out/1
  Black Box/6 -> qv/1
  rd1_i/1 -> Black Box/1
  r1_clk90/1 -> Black Box/2
  r1_clk180/1 -> Black Box/3
  r1_clk270/1 -> Black Box/4
  r1_rst/1 -> Black Box/10
  Black Box/5 -> q/1
  Black Box/1 -> ra1/1
  Black Box/2 -> rc1/1
  Black Box/3 -> rd1_o/1
  Black Box/4 -> rd1_t/1
  r/1 -> Black Box/8
  w/1 -> Black Box/9
  a/1 -> Black Box/5
  d/1 -> Black Box/6
  be/1 -> Black Box/7
  Constant/1 -> r1_clk90/1, r1_clk180/1, r1_clk270/1, r1_rst/1, rd1_i/1
  rd1_o/1 -> Terminator/1
  rd1_t/1 -> Terminator1/1
  ra1/1 -> Terminator2/1
  rc1/1 -> Terminator3/1

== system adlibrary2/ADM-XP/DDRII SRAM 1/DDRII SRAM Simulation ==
  d : Inport  Port=1  LatchInput=off
  a : Inport  Port=2  LatchInput=off
  w : Inport  Port=3  LatchInput=off
  r : Inport  Port=4  LatchInput=off
  be : Inport  Port=5  LatchInput=off
  Concat : xbsIndex_r3/Concat  num_inputs=2  explicit_period=off  period=1  dbl_ovrd=off
  Disregard Subsystem : xbsIndex_r3/Disregard Subsystem  Tag=discardX
  Gateway In1 : xbsIndex_r3/Gateway In  arith_type=Unsigned  n_bits=32  bin_pt=0  quantization=Truncate  overflow=Wrap  period=1  timing_constraint=None  locs_specified=off  LOCs={}  needs_fixed_name=off  dbl_ovrd=on  show_param=off
  Gateway In6 : xbsIndex_r3/Gateway In  arith_type=Boolean  n_bits=1  bin_pt=0  quantization=Truncate  overflow=Wrap  period=1  timing_constraint=None  locs_specified=off  LOCs={}  needs_fixed_name=off  dbl_ovrd=on  show_param=off
  Gateway In7 : xbsIndex_r3/Gateway In  arith_type=Unsigned  n_bits=32  bin_pt=0  quantization=Truncate  overflow=Wrap  period=1  timing_constraint=None  locs_specified=off  LOCs={}  needs_fixed_name=off  dbl_ovrd=on  show_param=off
  Gateway Out{,1..5} (6 alike) : xbsIndex_r3/Gateway Out  output_type=Double  nbits=8  bin_pt=6  arith_type=Boolean  quantization=Truncate  overflow=Wrap  hdl_port=off  timing_constraint=None  locs_specified=off  LOCs={}  needs_fixed_name=off  show_param=off
  S-Function : S-Function  FunctionName=d2sram  Parameters=1
  Slice : xbsIndex_r3/Slice  mode=Lower Bit Location + Width  nbits=32  bit1=0  base1=MSB of Input  bit0=0  base0=LSB of Input  boolean_output=off  explicit_period=off  period=1  dbl_ovrd=off
  Slice1 : xbsIndex_r3/Slice  mode=Lower Bit Location + Width  nbits=32  bit1=0  base1=MSB of Input  bit0=32  base0=LSB of Input  boolean_output=off  explicit_period=off  period=1  dbl_ovrd=off
  q : Outport
  qv : Outport  Port=2
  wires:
  a/1 -> Gateway Out2/1
  w/1 -> Gateway Out3/1
  S-Function/1 -> Gateway In7/1
  Gateway Out/1 -> S-Function/1
  Gateway Out1/1 -> S-Function/2
  Gateway Out2/1 -> S-Function/3
  Gateway Out3/1 -> S-Function/4
  r/1 -> Gateway Out4/1
  Gateway Out4/1 -> S-Function/5
  S-Function/2 -> Gateway In1/1
  Gateway In6/1 -> qv/1
  S-Function/3 -> Gateway In6/1
  be/1 -> Gateway Out5/1
  Gateway Out5/1 -> S-Function/6
  Slice1/1 -> Gateway Out/1
  Slice/1 -> Gateway Out1/1
  d/1 -> Slice1/1, Slice/1
  Gateway In7/1 -> Concat/1
  Gateway In1/1 -> Concat/2
  Concat/1 -> q/1

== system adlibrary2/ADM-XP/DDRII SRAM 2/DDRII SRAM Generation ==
  d : Inport  Port=1  LatchInput=off
  a : Inport  Port=2  LatchInput=off
  w : Inport  Port=3  LatchInput=off
  r : Inport  Port=4  LatchInput=off
  be : Inport  Port=5  LatchInput=off
  adlocb_in : Inport  Port=6  LatchInput=off
  Black Box : S-Function  FunctionName=xlblackbox2  Parameters=sfcn_mwsv__  mask(Xilinx Blackbox Block){init_code=d2sram_config, sim_method=Inactive, engine_block=, show_param=off, xl_area=[0, 0, 0, 0, 0, 0, 0], xl_use_area=off, adlocb_devid=2}
      mask prompts: init_code "Block Configuration M-Function"; sim_method "Simulation Mode"; engine_block "HDL Co-Simulator To Use  (specify helper block by name)"; show_param "---------------------- Show Implementation Parameters -----------------------------------------------------------------------------------"; xl_area "FPGA Area [Slices, FFs, BRAMs, LUTs, IOBs, Emb. Mults, TBUFs]"; xl_use_area "Use Area Above For Estimation"; adlocb_devid "ADLOCB DEV ID"
      mask help: Incorporates black box HDL and simulation model into a System Generator design. You must supply a Black Box with certain information about the HDL component you would like to bring into System Generator. This information is provided through a Matlab function. When "Simulation Mode" is set to "Inactive," you will typically want to provide a separate simulation model by using a Simulation Multiplexer. When "Simulation Mode" is set to "Use HDL Co-Simulation", you must include a ModelSim block in the design.
      mask init:
      | [designRoot, family, part, speed, package, simulinkPeriod, sysclkPeriod, dbl_ovrd, trimVbit] = xlSysgenSettings(gcb,0,0);
      | 
      | [bg,fg] = xlcmap('XBlock');
      | iPos = get_param(gcb,'Position');
      | iWidth=iPos(3)-iPos(1); iHeight=iPos(4)-iPos(2);
      | iCx=iWidth/2;
      | iCy=iHeight/2;
      | [logoX, logoY] = xlogo(iPos);
      | zstr='z'; zpstr='-1';
      | zstrx = iCx-3; if (zstrx<16) zstr='';zpstr=''; end
      | zstry = iCy;
      | 
      | precision0 = 1;
      | latency = 0;
      | dblOvrd = 0;
      | 
      | mdlPath = xlGetMdlDir(bdroot);
      | 
      | refBlk = get_param(gcb,'referenceBlock');
      | if (isempty(refBlk) | strncmp(refBlk,'xbsIndex',8))
      | 	srcPath = mdlPath;
      | else
      | 	srcPath = xlPathToReference;
      | 	if (isempty(srcPath))
      | 		srcPath = mdlPath;
      | 	end
      | end
      | 
      | if (sim_method==2)
      | 	validEngineBlock = 0;
      | 	try
      | 	  engineBlock = xlBlockNameRelPath(get_param(gcb,'Parent'),engine_block);
      | 	catch
      | 	  engineBlock = '//';
      | 	end
      | 	try 
      | 	  engineWorkDir = get_param(engineBlock,'dir');
      | 	  validEngineBlock = 1;
      | 	catch
      | 	end
      | end
      | 
      | % just pass everything to s-function
      | sfcn_mwsv__ = get_param(gcb, 'MaskWSVariables');
      | 
      | plabel = xlbbPortLabelStruct(gcb,init_code,mdlPath);
  Constant : Constant  Value=0
  Convert : xbsIndex_r3/Convert  arith_type=Unsigned  n_bits=66  bin_pt=0  quantization=Truncate  overflow=Wrap  latency=0  explicit_period=on  period=1  dbl_ovrd=off  show_param=off  inserted_by_tool=off  pipeline=off
  Terminator{,1..3} (4 alike) : Terminator
  r2_clk180 : xbsIndex_r3/Gateway In  arith_type=Boolean  n_bits=1  bin_pt=0  quantization=Truncate  overflow=Wrap  period=1  timing_constraint=None  locs_specified=off  LOCs={}  needs_fixed_name=off  dbl_ovrd=off  show_param=off
  r2_clk270 : xbsIndex_r3/Gateway In  arith_type=Boolean  n_bits=1  bin_pt=0  quantization=Truncate  overflow=Wrap  period=1  timing_constraint=None  locs_specified=off  LOCs={}  needs_fixed_name=off  dbl_ovrd=off  show_param=off
  r2_clk90 : xbsIndex_r3/Gateway In  arith_type=Boolean  n_bits=1  bin_pt=0  quantization=Truncate  overflow=Wrap  period=1  timing_constraint=None  locs_specified=off  LOCs={}  needs_fixed_name=off  dbl_ovrd=off  show_param=off
  r2_rst : xbsIndex_r3/Gateway In  arith_type=Boolean  n_bits=1  bin_pt=0  quantization=Truncate  overflow=Wrap  period=1  timing_constraint=None  locs_specified=off  LOCs={}  needs_fixed_name=off  dbl_ovrd=off  show_param=off
  ra2 : xbsIndex_r3/Gateway Out  output_type=Double  nbits=8  bin_pt=6  arith_type=Boolean  quantization=Truncate  overflow=Wrap  hdl_port=on  timing_constraint=None  locs_specified=off  LOCs={}  needs_fixed_name=off  show_param=off
  rc2 : xbsIndex_r3/Gateway Out  output_type=Double  nbits=8  bin_pt=6  arith_type=Boolean  quantization=Truncate  overflow=Wrap  hdl_port=on  timing_constraint=None  locs_specified=off  LOCs={}  needs_fixed_name=off  show_param=off
  rd2_i : xbsIndex_r3/Gateway In  arith_type=Unsigned  n_bits=32  bin_pt=0  quantization=Truncate  overflow=Wrap  period=1  timing_constraint=None  locs_specified=off  LOCs={}  needs_fixed_name=off  dbl_ovrd=off  show_param=off
  rd2_o : xbsIndex_r3/Gateway Out  output_type=Double  nbits=8  bin_pt=6  arith_type=Boolean  quantization=Truncate  overflow=Wrap  hdl_port=on  timing_constraint=None  locs_specified=off  LOCs={}  needs_fixed_name=off  show_param=off
  rd2_t : xbsIndex_r3/Gateway Out  output_type=Double  nbits=8  bin_pt=6  arith_type=Boolean  quantization=Truncate  overflow=Wrap  hdl_port=on  timing_constraint=None  locs_specified=off  LOCs={}  needs_fixed_name=off  show_param=off
  q : Outport
  qv : Outport  Port=2
  adlocb_out : Outport  Port=3
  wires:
  Black Box/7 -> Convert/1
  adlocb_in/1 -> Black Box/11
  Convert/1 -> adlocb_out/1
  Black Box/6 -> qv/1
  rd2_i/1 -> Black Box/1
  r2_clk90/1 -> Black Box/2
  r2_clk180/1 -> Black Box/3
  r2_clk270/1 -> Black Box/4
  r2_rst/1 -> Black Box/10
  Black Box/5 -> q/1
  Black Box/1 -> ra2/1
  Black Box/2 -> rc2/1
  Black Box/3 -> rd2_o/1
  Black Box/4 -> rd2_t/1
  r/1 -> Black Box/8
  w/1 -> Black Box/9
  a/1 -> Black Box/5
  d/1 -> Black Box/6
  be/1 -> Black Box/7
  Constant/1 -> r2_clk90/1, r2_clk180/1, r2_clk270/1, r2_rst/1, rd2_i/1
  rd2_o/1 -> Terminator/1
  rd2_t/1 -> Terminator1/1
  ra2/1 -> Terminator2/1
  rc2/1 -> Terminator3/1
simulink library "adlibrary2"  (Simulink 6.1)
undefined symbols (not defined in the file or in its folder): adlibrary2, ADM, Bit, Black, Box, d2sram_config, DDR, ddr32_config, Generation, II, Inactive, Location, Lower, SDRAM, Simulation, Subsystem, Width, xbsIndex_r3, XPL, XRC, XRM, zbt32_config, zbt64_config
libraries: xbsIndex_r3 x633
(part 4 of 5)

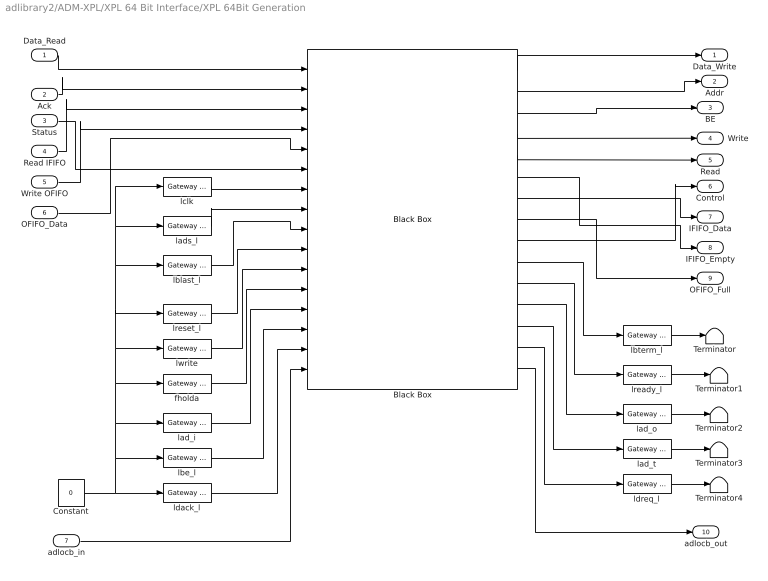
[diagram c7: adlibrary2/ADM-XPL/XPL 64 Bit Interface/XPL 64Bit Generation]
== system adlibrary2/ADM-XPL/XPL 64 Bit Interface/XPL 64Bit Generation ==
  Data_Read : Inport  Port=1  LatchInput=off
  Ack : Inport  Port=2  LatchInput=off
  Status : Inport  Port=3  LatchInput=off
  Read IFIFO : Inport  Port=4  LatchInput=off
  Write OFIFO : Inport  Port=5  LatchInput=off
  OFIFO_Data : Inport  Port=6  LatchInput=off
  adlocb_in : Inport  Port=7  LatchInput=off
  Black Box : xbsIndex_r3/Black Box  init_code=lbif64_xpl_config  sim_method=Inactive  show_param=on
  Constant : Constant  Value=0
  Terminator{,1..4} (5 alike) : Terminator
  fholda : xbsIndex_r3/Gateway In  arith_type=Boolean  n_bits=8  bin_pt=6  quantization=Truncate  overflow=Wrap  period=1  timing_constraint=None  locs_specified=off  LOCs={}  needs_fixed_name=off  dbl_ovrd=off  show_param=off
  lad_i : xbsIndex_r3/Gateway In  arith_type=Unsigned  n_bits=64  bin_pt=0  quantization=Truncate  overflow=Wrap  period=1  timing_constraint=None  locs_specified=off  LOCs={}  needs_fixed_name=off  dbl_ovrd=off  show_param=off
  lad_o : xbsIndex_r3/Gateway Out  output_type=Double  nbits=8  bin_pt=6  arith_type=Boolean  quantization=Truncate  overflow=Wrap  hdl_port=on  timing_constraint=None  locs_specified=off  LOCs={}  needs_fixed_name=off  show_param=off
  lad_t : xbsIndex_r3/Gateway Out  output_type=Double  nbits=8  bin_pt=6  arith_type=Boolean  quantization=Truncate  overflow=Wrap  hdl_port=on  timing_constraint=None  locs_specified=off  LOCs={}  needs_fixed_name=off  show_param=off
  lads_l : xbsIndex_r3/Gateway In  arith_type=Boolean  n_bits=8  bin_pt=6  quantization=Truncate  overflow=Wrap  period=1  timing_constraint=None  locs_specified=off  LOCs={}  needs_fixed_name=off  dbl_ovrd=off  show_param=off
  lbe_l : xbsIndex_r3/Gateway In  arith_type=Unsigned  n_bits=8  bin_pt=0  quantization=Truncate  overflow=Wrap  period=1  timing_constraint=None  locs_specified=off  LOCs={}  needs_fixed_name=off  dbl_ovrd=off  show_param=off
  lblast_l : xbsIndex_r3/Gateway In  arith_type=Boolean  n_bits=8  bin_pt=6  quantization=Truncate  overflow=Wrap  period=1  timing_constraint=None  locs_specified=off  LOCs={}  needs_fixed_name=off  dbl_ovrd=off  show_param=off
  lbterm_l : xbsIndex_r3/Gateway Out  output_type=Double  nbits=8  bin_pt=6  arith_type=Boolean  quantization=Truncate  overflow=Wrap  hdl_port=on  timing_constraint=None  locs_specified=off  LOCs={}  needs_fixed_name=off  show_param=off
  lclk : xbsIndex_r3/Gateway In  arith_type=Boolean  n_bits=8  bin_pt=6  quantization=Truncate  overflow=Wrap  period=1  timing_constraint=None  locs_specified=off  LOCs={}  needs_fixed_name=off  dbl_ovrd=off  show_param=off
  ldack_l : xbsIndex_r3/Gateway In  arith_type=Unsigned  n_bits=2  bin_pt=0  quantization=Truncate  overflow=Wrap  period=1  timing_constraint=None  locs_specified=off  LOCs={}  needs_fixed_name=off  dbl_ovrd=off  show_param=off
  ldreq_l : xbsIndex_r3/Gateway Out  output_type=Double  nbits=8  bin_pt=6  arith_type=Boolean  quantization=Truncate  overflow=Wrap  hdl_port=on  timing_constraint=None  locs_specified=off  LOCs={}  needs_fixed_name=off  show_param=off
  lready_l : xbsIndex_r3/Gateway Out  output_type=Double  nbits=8  bin_pt=6  arith_type=Boolean  quantization=Truncate  overflow=Wrap  hdl_port=on  timing_constraint=None  locs_specified=off  LOCs={}  needs_fixed_name=off  show_param=off
  lreset_l : xbsIndex_r3/Gateway In  arith_type=Boolean  n_bits=8  bin_pt=6  quantization=Truncate  overflow=Wrap  period=1  timing_constraint=None  locs_specified=off  LOCs={}  needs_fixed_name=off  dbl_ovrd=off  show_param=off
  lwrite : xbsIndex_r3/Gateway In  arith_type=Boolean  n_bits=8  bin_pt=6  quantization=Truncate  overflow=Wrap  period=1  timing_constraint=None  locs_specified=off  LOCs={}  needs_fixed_name=off  dbl_ovrd=off  show_param=off
  Data_Write : Outport
  Addr : Outport  Port=2
  BE : Outport  Port=3
  Write : Outport  Port=4
  Read : Outport  Port=5
  Control : Outport  Port=6
  IFIFO_Data : Outport  Port=7
  IFIFO_Empty : Outport  Port=8
  OFIFO_Full : Outport  Port=9
  adlocb_out : Outport  Port=10
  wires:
  lbe_l/1 -> Black Box/14
  Data_Read/1 -> Black Box/1
  Ack/1 -> Black Box/2
  Status/1 -> Black Box/6
  Read IFIFO/1 -> Black Box/3
  Write OFIFO/1 -> Black Box/4
  OFIFO_Data/1 -> Black Box/5
  Black Box/1 -> Data_Write/1
  Black Box/2 -> Addr/1
  lclk/1 -> Black Box/7
  lads_l/1 -> Black Box/8
  lblast_l/1 -> Black Box/9
  lreset_l/1 -> Black Box/10
  lwrite/1 -> Black Box/11
  fholda/1 -> Black Box/12
  lad_i/1 -> Black Box/13
  ldack_l/1 -> Black Box/15
  Constant/1 -> ldack_l/1, lclk/1, lads_l/1, lblast_l/1, lreset_l/1, lwrite/1, fholda/1, lad_i/1, lbe_l/1
  lbterm_l/1 -> Terminator/1
  lready_l/1 -> Terminator1/1
  lad_o/1 -> Terminator2/1
  lad_t/1 -> Terminator3/1
  ldreq_l/1 -> Terminator4/1
  Black Box/14 -> ldreq_l/1
  Black Box/3 -> BE/1
  Black Box/4 -> Write/1
  Black Box/5 -> Read/1
  Black Box/6 -> IFIFO_Empty/1
  Black Box/7 -> IFIFO_Data/1
  Black Box/8 -> OFIFO_Full/1
  Black Box/9 -> Control/1
  Black Box/10 -> lbterm_l/1
  Black Box/11 -> lready_l/1
  Black Box/12 -> lad_o/1
  Black Box/13 -> lad_t/1
  Black Box/15 -> adlocb_out/1
  adlocb_in/1 -> Black Box/16

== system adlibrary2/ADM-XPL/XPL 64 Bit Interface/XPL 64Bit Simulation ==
  Data_Read : Inport  Port=1  LatchInput=off
  Ack : Inport  Port=2  LatchInput=off
  Status : Inport  Port=3  LatchInput=off
  Read IFIFO : Inport  Port=4  LatchInput=off
  Write OFIFO : Inport  Port=5  LatchInput=off
  OFIFO_Data : Inport  Port=6  LatchInput=off
  Disregard Subsystem : xbsIndex_r3/Disregard Subsystem  Tag=discardX
  Gateway Out{,1..8} (9 alike) : xbsIndex_r3/Gateway Out  hdl_port=off  timing_constraint=None  locs_specified=off  LOCs={}  needs_fixed_name=off  show_param=off
  S-Function : S-Function  FunctionName=lbif_xpl64  Parameters=program,clock_ratio
  Slice : xbsIndex_r3/Slice  mode=Lower Bit Location + Width  nbits=32  bit1=0  base1=MSB of Input  bit0=0  base0=LSB of Input  boolean_output=off  explicit_period=off  period=1  dbl_ovrd=off
  Slice1 : xbsIndex_r3/Slice  mode=Lower Bit Location + Width  nbits=32  bit1=0  base1=MSB of Input  bit0=32  base0=LSB of Input  boolean_output=off  explicit_period=off  period=1  dbl_ovrd=off
  Slice2 : xbsIndex_r3/Slice  mode=Lower Bit Location + Width  nbits=32  bit1=0  base1=MSB of Input  bit0=0  base0=LSB of Input  boolean_output=off  explicit_period=off  period=1  dbl_ovrd=off
  Slice3 : xbsIndex_r3/Slice  mode=Lower Bit Location + Width  nbits=32  bit1=0  base1=MSB of Input  bit0=32  base0=LSB of Input  boolean_output=off  explicit_period=off  period=1  dbl_ovrd=off
  Slice4 : xbsIndex_r3/Slice  mode=Lower Bit Location + Width  nbits=32  bit1=0  base1=MSB of Input  bit0=0  base0=LSB of Input  boolean_output=off  explicit_period=off  period=1  dbl_ovrd=off
  Slice5 : xbsIndex_r3/Slice  mode=Lower Bit Location + Width  nbits=32  bit1=0  base1=MSB of Input  bit0=32  base0=LSB of Input  boolean_output=off  explicit_period=off  period=1  dbl_ovrd=off
  Subsystem : Subsystem
  Data_Write : Outport
  Addr : Outport  Port=2
  BE : Outport  Port=3
  Write : Outport  Port=4
  Read : Outport  Port=5
  Control : Outport  Port=6
  IFIFO_Data : Outport  Port=7
  IFIFO_Empty : Outport  Port=8
  OFIFO_Full : Outport  Port=9
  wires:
  Data_Read/1 -> Slice/1, Slice1/1
  Ack/1 -> Gateway Out1/1
  Status/1 -> Slice2/1, Slice3/1
  Read IFIFO/1 -> Gateway Out3/1
  Write OFIFO/1 -> Gateway Out4/1
  OFIFO_Data/1 -> Slice4/1, Slice5/1
  Slice/1 -> Gateway Out/1
  Slice1/1 -> Gateway Out6/1
  Gateway Out/1 -> S-Function/1
  Gateway Out6/1 -> S-Function/2
  Gateway Out1/1 -> S-Function/3
  Slice2/1 -> Gateway Out2/1
  Slice3/1 -> Gateway Out7/1
  Gateway Out2/1 -> S-Function/4
  Gateway Out7/1 -> S-Function/5
  Gateway Out3/1 -> S-Function/6
  Gateway Out4/1 -> S-Function/7
  Slice4/1 -> Gateway Out5/1
  Slice5/1 -> Gateway Out8/1
  Gateway Out5/1 -> S-Function/8
  Gateway Out8/1 -> S-Function/9
  S-Function/1 -> Subsystem/1(data_write0)
  S-Function/2 -> Subsystem/2(data_write1)
  S-Function/3 -> Subsystem/3(addr)
  S-Function/4 -> Subsystem/4(be)
  S-Function/5 -> Subsystem/5(write)
  S-Function/6 -> Subsystem/6(read)
  S-Function/7 -> Subsystem/7(control0)
  S-Function/8 -> Subsystem/8(control1)
  S-Function/9 -> Subsystem/9(ififo_data0)
  S-Function/12 -> Subsystem/12(ofifo_full)
  S-Function/11 -> Subsystem/11(ififo_empty)
  S-Function/10 -> Subsystem/10(ififo_data1)
  Subsystem/9(Out9) -> OFIFO_Full/1
  Subsystem/8(Out8) -> IFIFO_Empty/1
  Subsystem/7(Out7) -> IFIFO_Data/1
  Subsystem/6(Out6) -> Control/1
  Subsystem/5(Out5) -> Read/1
  Subsystem/4(Out4) -> Write/1
  Subsystem/3(Out3) -> BE/1
  Subsystem/2(Out2) -> Addr/1
  Subsystem/1(Out1) -> Data_Write/1

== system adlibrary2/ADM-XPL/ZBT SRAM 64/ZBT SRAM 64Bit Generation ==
  d : Inport  Port=1  LatchInput=off
  a : Inport  Port=2  LatchInput=off
  w : Inport  Port=3  LatchInput=off
  r : Inport  Port=4  LatchInput=off
  be : Inport  Port=5  LatchInput=off
  adlocb_in : Inport  Port=6  LatchInput=off
  Black Box : S-Function  AncestorBlock=xbsIndex_r3/Black Box  FunctionName=xlblackbox2  Parameters=sfcn_mwsv__  mask(Xilinx Blackbox Block){init_code=zbt64_config, sim_method=Inactive, engine_block=, show_param=on, xl_area=[155, 230, 0, 75, 0, 0, 0], xl_use_area=off, adlocb_devid=0}
      mask prompts: init_code "Block Configuration M-Function"; sim_method "Simulation Mode"; engine_block "HDL Co-Simulator To Use  (specify helper block by name)"; show_param "---------------------- Show Implementation Parameters -----------------------------------------------------------------------------------"; xl_area "FPGA Area [Slices, FFs, BRAMs, LUTs, IOBs, Emb. Mults, TBUFs]"; xl_use_area "Use Area Above For Estimation"; adlocb_devid "ADLOCB DEV ID"
      mask help: Incorporates black box HDL and simulation model into a System Generator design. You must supply a Black Box with certain information about the HDL component you would like to bring into System Generator. This information is provided through a Matlab function. When "Simulation Mode" is set to "Inactive," you will typically want to provide a separate simulation model by using a Simulation Multiplexer. When "Simulation Mode" is set to "Use HDL Co-Simulation", you must include a ModelSim block in the design.
      mask init:
      | [designRoot, family, part, speed, package, simulinkPeriod, sysclkPeriod, dbl_ovrd, trimVbit] = xlSysgenSettings(gcb,0,0);
      | 
      | [bg,fg] = xlcmap('XBlock');
      | iPos = get_param(gcb,'Position');
      | iWidth=iPos(3)-iPos(1); iHeight=iPos(4)-iPos(2);
      | iCx=iWidth/2;
      | iCy=iHeight/2;
      | [logoX, logoY] = xlogo(iPos);
      | zstr='z'; zpstr='-1';
      | zstrx = iCx-3; if (zstrx<16) zstr='';zpstr=''; end
      | zstry = iCy;
      | 
      | precision0 = 1;
      | latency = 0;
      | dblOvrd = 0;
      | 
      | mdlPath = xlGetMdlDir(bdroot);
      | 
      | refBlk = get_param(gcb,'referenceBlock');
      | if (isempty(refBlk) | strncmp(refBlk,'xbsIndex',8))
      | 	srcPath = mdlPath;
      | else
      | 	srcPath = xlPathToReference;
      | 	if (isempty(srcPath))
      | 		srcPath = mdlPath;
      | 	end
      | end
      | 
      | if (sim_method==2)
      | 	validEngineBlock = 0;
      | 	try
      | 	  engineBlock = xlBlockNameRelPath(get_param(gcb,'Parent'),engine_block);
      | 	catch
      | 	  engineBlock = '//';
      | 	end
      | 	try 
      | 	  engineWorkDir = get_param(engineBlock,'dir');
      | 	  validEngineBlock = 1;
      | 	catch
      | 	end
      | end
      | 
      | % just pass everything to s-function
      | sfcn_mwsv__ = get_param(gcb, 'MaskWSVariables');
      | 
      | plabel = xlbbPortLabelStruct(gcb,init_code,mdlPath);
  Constant : Constant  Value=0
  Convert : xbsIndex_r3/Convert  arith_type=Unsigned  n_bits=66  bin_pt=0  quantization=Truncate  overflow=Wrap  latency=0  explicit_period=on  period=1  dbl_ovrd=off  show_param=off  inserted_by_tool=off  pipeline=off
  Terminator{,1..3} (4 alike) : Terminator
  ra0 : xbsIndex_r3/Gateway Out  output_type=Double  nbits=8  bin_pt=6  arith_type=Boolean  quantization=Truncate  overflow=Wrap  hdl_port=on  timing_constraint=None  locs_specified=off  LOCs={}  needs_fixed_name=off  show_param=off
  rc0 : xbsIndex_r3/Gateway Out  output_type=Double  nbits=8  bin_pt=6  arith_type=Boolean  quantization=Truncate  overflow=Wrap  hdl_port=on  timing_constraint=None  locs_specified=off  LOCs={}  needs_fixed_name=off  show_param=off
  rd0_i : xbsIndex_r3/Gateway In  arith_type=Unsigned  n_bits=64  bin_pt=0  quantization=Truncate  overflow=Wrap  period=1  timing_constraint=None  locs_specified=off  LOCs={}  needs_fixed_name=off  dbl_ovrd=off  show_param=off
  rd0_o : xbsIndex_r3/Gateway Out  output_type=Double  nbits=8  bin_pt=6  arith_type=Boolean  quantization=Truncate  overflow=Wrap  hdl_port=on  timing_constraint=None  locs_specified=off  LOCs={}  needs_fixed_name=off  show_param=off
  rd0_t : xbsIndex_r3/Gateway Out  output_type=Double  nbits=8  bin_pt=6  arith_type=Boolean  quantization=Truncate  overflow=Wrap  hdl_port=on  timing_constraint=None  locs_specified=off  LOCs={}  needs_fixed_name=off  show_param=off
  q : Outport
  qv : Outport  Port=2
  adlocb_out : Outport  Port=3
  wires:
  d/1 -> Black Box/1
  Black Box/1 -> q/1
  rd0_i/1 -> Black Box/6
  Constant/1 -> rd0_i/1
  rd0_o/1 -> Terminator/1
  rd0_t/1 -> Terminator1/1
  ra0/1 -> Terminator2/1
  rc0/1 -> Terminator3/1
  a/1 -> Black Box/2
  w/1 -> Black Box/3
  r/1 -> Black Box/4
  be/1 -> Black Box/5
  Black Box/2 -> qv/1
  Black Box/3 -> rd0_o/1
  Black Box/4 -> rd0_t/1
  Black Box/5 -> ra0/1
  Black Box/6 -> rc0/1
  adlocb_in/1 -> Black Box/7
  Black Box/7 -> Convert/1
  Convert/1 -> adlocb_out/1

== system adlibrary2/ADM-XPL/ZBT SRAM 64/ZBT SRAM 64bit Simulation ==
  d : Inport  Port=1  LatchInput=off
  a : Inport  Port=2  LatchInput=off
  w : Inport  Port=3  LatchInput=off
  r : Inport  Port=4  LatchInput=off
  be : Inport  Port=5  LatchInput=off
  Concat : xbsIndex_r3/Concat  num_inputs=2  explicit_period=off  period=1  dbl_ovrd=off
  Disregard Subsystem : xbsIndex_r3/Disregard Subsystem  Tag=discardX
  Gateway In1 : xbsIndex_r3/Gateway In  arith_type=Unsigned  n_bits=32  bin_pt=0  quantization=Truncate  overflow=Wrap  period=1  timing_constraint=None  locs_specified=off  LOCs={}  needs_fixed_name=off  dbl_ovrd=on  show_param=off
  Gateway In6 : xbsIndex_r3/Gateway In  arith_type=Boolean  n_bits=1  bin_pt=0  quantization=Truncate  overflow=Wrap  period=1  timing_constraint=None  locs_specified=off  LOCs={}  needs_fixed_name=off  dbl_ovrd=on  show_param=off
  Gateway In7 : xbsIndex_r3/Gateway In  arith_type=Unsigned  n_bits=32  bin_pt=0  quantization=Truncate  overflow=Wrap  period=1  timing_constraint=None  locs_specified=off  LOCs={}  needs_fixed_name=off  dbl_ovrd=on  show_param=off
  Gateway Out{,1..5} (6 alike) : xbsIndex_r3/Gateway Out  output_type=Double  nbits=8  bin_pt=6  arith_type=Boolean  quantization=Truncate  overflow=Wrap  hdl_port=off  timing_constraint=None  locs_specified=off  LOCs={}  needs_fixed_name=off  show_param=off
  S-Function : S-Function  FunctionName=zbt64  Parameters=0
  Slice : xbsIndex_r3/Slice  mode=Lower Bit Location + Width  nbits=32  bit1=0  base1=MSB of Input  bit0=0  base0=LSB of Input  boolean_output=off  explicit_period=off  period=1  dbl_ovrd=off
  Slice1 : xbsIndex_r3/Slice  mode=Lower Bit Location + Width  nbits=32  bit1=0  base1=MSB of Input  bit0=32  base0=LSB of Input  boolean_output=off  explicit_period=off  period=1  dbl_ovrd=off
  q : Outport
  qv : Outport  Port=2
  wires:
  a/1 -> Gateway Out2/1
  w/1 -> Gateway Out3/1
  S-Function/1 -> Gateway In7/1
  Gateway Out/1 -> S-Function/1
  Gateway Out1/1 -> S-Function/2
  Gateway Out2/1 -> S-Function/3
  Gateway Out3/1 -> S-Function/4
  r/1 -> Gateway Out4/1
  Gateway Out4/1 -> S-Function/5
  S-Function/2 -> Gateway In1/1
  Gateway In6/1 -> qv/1
  S-Function/3 -> Gateway In6/1
  be/1 -> Gateway Out5/1
  Gateway Out5/1 -> S-Function/6
  Slice1/1 -> Gateway Out/1
  Slice/1 -> Gateway Out1/1
  d/1 -> Slice1/1, Slice/1
  Gateway In7/1 -> Concat/1
  Gateway In1/1 -> Concat/2
  Concat/1 -> q/1

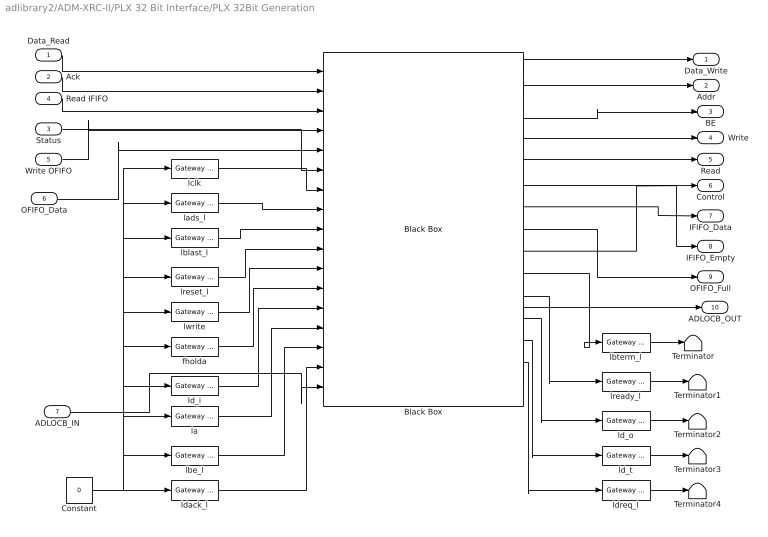
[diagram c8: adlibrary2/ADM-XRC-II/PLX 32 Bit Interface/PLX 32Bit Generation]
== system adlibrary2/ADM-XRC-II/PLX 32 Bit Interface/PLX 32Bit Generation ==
  Data_Read : Inport  Port=1  LatchInput=off
  Ack : Inport  Port=2  LatchInput=off
  Status : Inport  Port=3  LatchInput=off
  Read IFIFO : Inport  Port=4  LatchInput=off
  Write OFIFO : Inport  Port=5  LatchInput=off
  OFIFO_Data : Inport  Port=6  LatchInput=off
  ADLOCB_IN : Inport  Port=7  LatchInput=off
  Black Box : xbsIndex_r3/Black Box  init_code=lbif32_plx_config  sim_method=Inactive  show_param=on
  Constant : Constant  Value=0
  Terminator{,1..4} (5 alike) : Terminator
  fholda : xbsIndex_r3/Gateway In  arith_type=Boolean  n_bits=8  bin_pt=6  quantization=Truncate  overflow=Wrap  period=1  timing_constraint=None  locs_specified=off  LOCs={}  needs_fixed_name=off  dbl_ovrd=off  show_param=off
  la : xbsIndex_r3/Gateway In  arith_type=Unsigned  n_bits=24  bin_pt=0  quantization=Truncate  overflow=Wrap  period=1  timing_constraint=None  locs_specified=off  LOCs={}  needs_fixed_name=off  dbl_ovrd=off  show_param=off
  lads_l : xbsIndex_r3/Gateway In  arith_type=Boolean  n_bits=8  bin_pt=6  quantization=Truncate  overflow=Wrap  period=1  timing_constraint=None  locs_specified=off  LOCs={}  needs_fixed_name=off  dbl_ovrd=off  show_param=off
  lbe_l : xbsIndex_r3/Gateway In  arith_type=Unsigned  n_bits=4  bin_pt=0  quantization=Truncate  overflow=Wrap  period=1  timing_constraint=None  locs_specified=off  LOCs={}  needs_fixed_name=off  dbl_ovrd=off  show_param=off
  lblast_l : xbsIndex_r3/Gateway In  arith_type=Boolean  n_bits=8  bin_pt=6  quantization=Truncate  overflow=Wrap  period=1  timing_constraint=None  locs_specified=off  LOCs={}  needs_fixed_name=off  dbl_ovrd=off  show_param=off
  lbterm_l : xbsIndex_r3/Gateway Out  output_type=Double  nbits=8  bin_pt=6  arith_type=Boolean  quantization=Truncate  overflow=Wrap  hdl_port=on  timing_constraint=None  locs_specified=off  LOCs={}  needs_fixed_name=off  show_param=off
  lclk : xbsIndex_r3/Gateway In  arith_type=Boolean  n_bits=8  bin_pt=6  quantization=Truncate  overflow=Wrap  period=1  timing_constraint=None  locs_specified=off  LOCs={}  needs_fixed_name=off  dbl_ovrd=off  show_param=off
  ld_i : xbsIndex_r3/Gateway In  arith_type=Unsigned  n_bits=32  bin_pt=0  quantization=Truncate  overflow=Wrap  period=1  timing_constraint=None  locs_specified=off  LOCs={}  needs_fixed_name=off  dbl_ovrd=off  show_param=off
  ld_o : xbsIndex_r3/Gateway Out  output_type=Double  nbits=8  bin_pt=6  arith_type=Boolean  quantization=Truncate  overflow=Wrap  hdl_port=on  timing_constraint=None  locs_specified=off  LOCs={}  needs_fixed_name=off  show_param=off
  ld_t : xbsIndex_r3/Gateway Out  output_type=Double  nbits=8  bin_pt=6  arith_type=Boolean  quantization=Truncate  overflow=Wrap  hdl_port=on  timing_constraint=None  locs_specified=off  LOCs={}  needs_fixed_name=off  show_param=off
  ldack_l : xbsIndex_r3/Gateway In  arith_type=Unsigned  n_bits=2  bin_pt=0  quantization=Truncate  overflow=Wrap  period=1  timing_constraint=None  locs_specified=off  LOCs={}  needs_fixed_name=off  dbl_ovrd=off  show_param=off
  ldreq_l : xbsIndex_r3/Gateway Out  output_type=Double  nbits=8  bin_pt=6  arith_type=Boolean  quantization=Truncate  overflow=Wrap  hdl_port=on  timing_constraint=None  locs_specified=off  LOCs={}  needs_fixed_name=off  show_param=off
  lready_l : xbsIndex_r3/Gateway Out  output_type=Double  nbits=8  bin_pt=6  arith_type=Boolean  quantization=Truncate  overflow=Wrap  hdl_port=on  timing_constraint=None  locs_specified=off  LOCs={}  needs_fixed_name=off  show_param=off
  lreset_l : xbsIndex_r3/Gateway In  arith_type=Boolean  n_bits=8  bin_pt=6  quantization=Truncate  overflow=Wrap  period=1  timing_constraint=None  locs_specified=off  LOCs={}  needs_fixed_name=off  dbl_ovrd=off  show_param=off
  lwrite : xbsIndex_r3/Gateway In  arith_type=Boolean  n_bits=8  bin_pt=6  quantization=Truncate  overflow=Wrap  period=1  timing_constraint=None  locs_specified=off  LOCs={}  needs_fixed_name=off  dbl_ovrd=off  show_param=off
  Data_Write : Outport
  Addr : Outport  Port=2
  BE : Outport  Port=3
  Write : Outport  Port=4
  Read : Outport  Port=5
  Control : Outport  Port=6
  IFIFO_Data : Outport  Port=7
  IFIFO_Empty : Outport  Port=8
  OFIFO_Full : Outport  Port=9
  ADLOCB_OUT : Outport  Port=10
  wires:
  Data_Read/1 -> Black Box/1
  Write OFIFO/1 -> Black Box/4
  OFIFO_Data/1 -> Black Box/5
  lclk/1 -> Black Box/7
  lblast_l/1 -> Black Box/9
  lreset_l/1 -> Black Box/10
  lwrite/1 -> Black Box/11
  fholda/1 -> Black Box/12
  ld_i/1 -> Black Box/13
  la/1 -> Black Box/14
  lbe_l/1 -> Black Box/15
  ldack_l/1 -> Black Box/16
  Constant/1 -> ldack_l/1, lclk/1, lads_l/1, lblast_l/1, lreset_l/1, lwrite/1, fholda/1, ld_i/1, la/1, lbe_l/1
  lbterm_l/1 -> Terminator/1
  lready_l/1 -> Terminator1/1
  ld_o/1 -> Terminator2/1
  ld_t/1 -> Terminator3/1
  ldreq_l/1 -> Terminator4/1
  Black Box/1 -> Data_Write/1
  Black Box/2 -> Addr/1
  Black Box/3 -> BE/1
  Black Box/4 -> Write/1
  Black Box/5 -> Read/1
  Black Box/7 -> IFIFO_Data/1
  Black Box/8 -> OFIFO_Full/1
  Black Box/6 -> IFIFO_Empty/1
  Black Box/9 -> Control/1
  Black Box/10 -> lbterm_l/1
  Black Box/11 -> lready_l/1
  Black Box/12 -> ld_o/1
  Black Box/13 -> ld_t/1
  Black Box/14 -> ldreq_l/1
  Ack/1 -> Black Box/2
  Read IFIFO/1 -> Black Box/3
  lads_l/1 -> Black Box/8
  Status/1 -> Black Box/6
  ADLOCB_IN/1 -> Black Box/17
  Black Box/15 -> ADLOCB_OUT/1

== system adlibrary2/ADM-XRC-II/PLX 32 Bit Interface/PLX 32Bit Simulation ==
  Data_Read : Inport  Port=1  LatchInput=off
  Ack : Inport  Port=2  LatchInput=off
  Status : Inport  Port=3  LatchInput=off
  Read IFIFO : Inport  Port=4  LatchInput=off
  Write OFIFO : Inport  Port=5  LatchInput=off
  OFIFO_Data : Inport  Port=6  LatchInput=off
  Disregard Subsystem : xbsIndex_r3/Disregard Subsystem  Tag=discardX
  Gateway Out{,1..5} (6 alike) : xbsIndex_r3/Gateway Out  output_type=Double  nbits=8  bin_pt=6  arith_type=Boolean  quantization=Truncate  overflow=Wrap  hdl_port=off  timing_constraint=None  locs_specified=off  LOCs={}  needs_fixed_name=off  show_param=off
  S-Function : S-Function  FunctionName=lbif_plx32  Parameters=program,clock_ratio
  Subsystem : Subsystem
  Data_Write : Outport
  Addr : Outport  Port=2
  BE : Outport  Port=3
  Write : Outport  Port=4
  Read : Outport  Port=5
  Control : Outport  Port=6
  IFIFO_Data : Outport  Port=7
  IFIFO_Empty : Outport  Port=8
  OFIFO_Full : Outport  Port=9
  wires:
  Subsystem/2(Out2) -> Addr/1
  Subsystem/1(Out1) -> Data_Write/1
  S-Function/2 -> Subsystem/2(In2)
  S-Function/1 -> Subsystem/1(In1)
  Gateway Out5/1 -> S-Function/6
  Gateway Out4/1 -> S-Function/5
  Gateway Out3/1 -> S-Function/4
  Gateway Out2/1 -> S-Function/3
  Gateway Out1/1 -> S-Function/2
  Gateway Out/1 -> S-Function/1
  OFIFO_Data/1 -> Gateway Out5/1
  Write OFIFO/1 -> Gateway Out4/1
  Read IFIFO/1 -> Gateway Out3/1
  Status/1 -> Gateway Out2/1
  Ack/1 -> Gateway Out1/1
  Data_Read/1 -> Gateway Out/1
  S-Function/3 -> Subsystem/3(In9)
  Subsystem/3(Out9) -> BE/1
  S-Function/4 -> Subsystem/4(In3)
  S-Function/5 -> Subsystem/5(In4)
  S-Function/6 -> Subsystem/6(In5)
  S-Function/7 -> Subsystem/7(In6)
  S-Function/8 -> Subsystem/8(In7)
  S-Function/9 -> Subsystem/9(In8)
  Subsystem/4(Out3) -> Write/1
  Subsystem/5(Out4) -> Read/1
  Subsystem/6(Out5) -> Control/1
  Subsystem/7(Out6) -> IFIFO_Data/1
  Subsystem/8(Out7) -> IFIFO_Empty/1
  Subsystem/9(Out8) -> OFIFO_Full/1

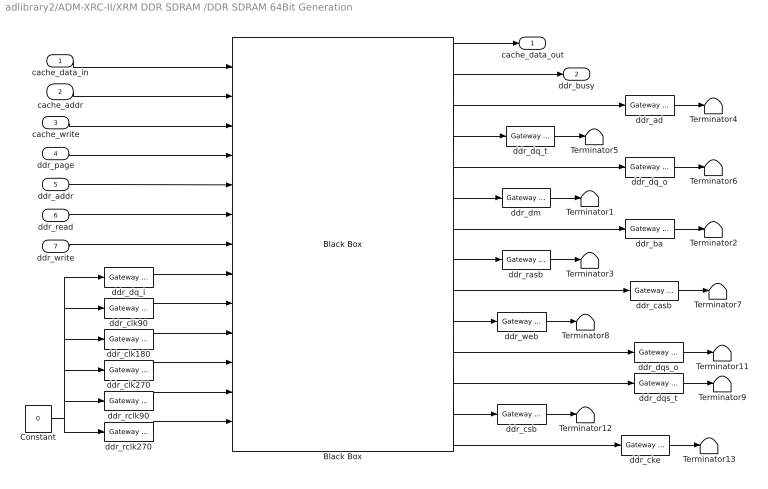
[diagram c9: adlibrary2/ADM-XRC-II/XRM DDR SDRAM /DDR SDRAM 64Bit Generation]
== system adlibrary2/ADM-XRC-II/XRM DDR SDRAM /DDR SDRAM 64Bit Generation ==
  cache_data_in : Inport  Port=1  LatchInput=off
  cache_addr : Inport  Port=2  LatchInput=off
  cache_write : Inport  Port=3  LatchInput=off
  ddr_page : Inport  Port=4  LatchInput=off
  ddr_addr : Inport  Port=5  LatchInput=off
  ddr_read : Inport  Port=6  LatchInput=off
  ddr_write : Inport  Port=7  LatchInput=off
  Black Box : xbsIndex_r3/Black Box  init_code=ddr64_config  sim_method=Inactive  show_param=on
  Constant : Constant  Value=0
  Terminator{1..9,11..13} (12 alike) : Terminator
  ddr_ad : xbsIndex_r3/Gateway Out  output_type=Double  nbits=8  bin_pt=6  arith_type=Boolean  quantization=Truncate  overflow=Wrap  hdl_port=on  timing_constraint=None  locs_specified=off  LOCs={}  needs_fixed_name=off  show_param=off
  ddr_ba : xbsIndex_r3/Gateway Out  output_type=Double  nbits=8  bin_pt=6  arith_type=Boolean  quantization=Truncate  overflow=Wrap  hdl_port=on  timing_constraint=None  locs_specified=off  LOCs={}  needs_fixed_name=off  show_param=off
  ddr_casb : xbsIndex_r3/Gateway Out  output_type=Double  nbits=8  bin_pt=6  arith_type=Boolean  quantization=Truncate  overflow=Wrap  hdl_port=on  timing_constraint=None  locs_specified=off  LOCs={}  needs_fixed_name=off  show_param=off
  ddr_cke : xbsIndex_r3/Gateway Out  output_type=Double  nbits=8  bin_pt=6  arith_type=Boolean  quantization=Truncate  overflow=Wrap  hdl_port=on  timing_constraint=None  locs_specified=off  LOCs={}  needs_fixed_name=off  show_param=off
  ddr_clk180 : xbsIndex_r3/Gateway In  arith_type=Boolean  n_bits=64  bin_pt=0  quantization=Truncate  overflow=Wrap  period=1  timing_constraint=None  locs_specified=off  LOCs={}  needs_fixed_name=off  dbl_ovrd=off  show_param=off
  ddr_clk270 : xbsIndex_r3/Gateway In  arith_type=Boolean  n_bits=64  bin_pt=0  quantization=Truncate  overflow=Wrap  period=1  timing_constraint=None  locs_specified=off  LOCs={}  needs_fixed_name=off  dbl_ovrd=off  show_param=off
  ddr_clk90 : xbsIndex_r3/Gateway In  arith_type=Boolean  n_bits=64  bin_pt=0  quantization=Truncate  overflow=Wrap  period=1  timing_constraint=None  locs_specified=off  LOCs={}  needs_fixed_name=off  dbl_ovrd=off  show_param=off
  ddr_csb : xbsIndex_r3/Gateway Out  output_type=Double  nbits=8  bin_pt=6  arith_type=Boolean  quantization=Truncate  overflow=Wrap  hdl_port=on  timing_constraint=None  locs_specified=off  LOCs={}  needs_fixed_name=off  show_param=off
  ddr_dm : xbsIndex_r3/Gateway Out  output_type=Double  nbits=8  bin_pt=6  arith_type=Boolean  quantization=Truncate  overflow=Wrap  hdl_port=on  timing_constraint=None  locs_specified=off  LOCs={}  needs_fixed_name=off  show_param=off
  ddr_dq_i : xbsIndex_r3/Gateway In  arith_type=Unsigned  n_bits=64  bin_pt=0  quantization=Truncate  overflow=Wrap  period=1  timing_constraint=None  locs_specified=off  LOCs={}  needs_fixed_name=off  dbl_ovrd=off  show_param=off
  ddr_dq_o : xbsIndex_r3/Gateway Out  output_type=Double  nbits=8  bin_pt=6  arith_type=Boolean  quantization=Truncate  overflow=Wrap  hdl_port=on  timing_constraint=None  locs_specified=off  LOCs={}  needs_fixed_name=off  show_param=off
  ddr_dq_t : xbsIndex_r3/Gateway Out  output_type=Double  nbits=8  bin_pt=6  arith_type=Boolean  quantization=Truncate  overflow=Wrap  hdl_port=on  timing_constraint=None  locs_specified=off  LOCs={}  needs_fixed_name=off  show_param=off
  ddr_dqs_o : xbsIndex_r3/Gateway Out  output_type=Double  nbits=8  bin_pt=6  arith_type=Boolean  quantization=Truncate  overflow=Wrap  hdl_port=on  timing_constraint=None  locs_specified=off  LOCs={}  needs_fixed_name=off  show_param=off
  ddr_dqs_t : xbsIndex_r3/Gateway Out  output_type=Double  nbits=8  bin_pt=6  arith_type=Boolean  quantization=Truncate  overflow=Wrap  hdl_port=on  timing_constraint=None  locs_specified=off  LOCs={}  needs_fixed_name=off  show_param=off
  ddr_rasb : xbsIndex_r3/Gateway Out  output_type=Double  nbits=8  bin_pt=6  arith_type=Boolean  quantization=Truncate  overflow=Wrap  hdl_port=on  timing_constraint=None  locs_specified=off  LOCs={}  needs_fixed_name=off  show_param=off
  ddr_rclk270 : xbsIndex_r3/Gateway In  arith_type=Boolean  n_bits=64  bin_pt=0  quantization=Truncate  overflow=Wrap  period=1  timing_constraint=None  locs_specified=off  LOCs={}  needs_fixed_name=off  dbl_ovrd=off  show_param=off
  ddr_rclk90 : xbsIndex_r3/Gateway In  arith_type=Boolean  n_bits=64  bin_pt=0  quantization=Truncate  overflow=Wrap  period=1  timing_constraint=None  locs_specified=off  LOCs={}  needs_fixed_name=off  dbl_ovrd=off  show_param=off
  ddr_web : xbsIndex_r3/Gateway Out  output_type=Double  nbits=8  bin_pt=6  arith_type=Boolean  quantization=Truncate  overflow=Wrap  hdl_port=on  timing_constraint=None  locs_specified=off  LOCs={}  needs_fixed_name=off  show_param=off
  cache_data_out : Outport
  ddr_busy : Outport  Port=2
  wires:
  Constant/1 -> ddr_clk90/1, ddr_dq_i/1, ddr_clk180/1, ddr_clk270/1, ddr_rclk90/1, ddr_rclk270/1
  ddr_clk90/1 -> Black Box/9
  ddr_dq_i/1 -> Black Box/8
  cache_data_in/1 -> Black Box/1
  cache_addr/1 -> Black Box/2
  cache_write/1 -> Black Box/3
  ddr_page/1 -> Black Box/4
  ddr_addr/1 -> Black Box/5
  ddr_read/1 -> Black Box/6
  ddr_write/1 -> Black Box/7
  Black Box/1 -> cache_data_out/1
  Black Box/2 -> ddr_busy/1
  ddr_ad/1 -> Terminator4/1
  ddr_dq_t/1 -> Terminator5/1
  ddr_dq_o/1 -> Terminator6/1
  ddr_dm/1 -> Terminator1/1
  ddr_ba/1 -> Terminator2/1
  ddr_rasb/1 -> Terminator3/1
  ddr_casb/1 -> Terminator7/1
  ddr_web/1 -> Terminator8/1
  ddr_dqs_o/1 -> Terminator11/1
  ddr_csb/1 -> Terminator12/1
  ddr_clk180/1 -> Black Box/10
  ddr_clk270/1 -> Black Box/11
  ddr_rclk90/1 -> Black Box/12
  ddr_rclk270/1 -> Black Box/13
  ddr_dqs_t/1 -> Terminator9/1
  ddr_cke/1 -> Terminator13/1
  Black Box/3 -> ddr_ad/1
  Black Box/4 -> ddr_dq_t/1
  Black Box/5 -> ddr_dq_o/1
  Black Box/6 -> ddr_dm/1
  Black Box/7 -> ddr_ba/1
  Black Box/8 -> ddr_rasb/1
  Black Box/9 -> ddr_casb/1
  Black Box/10 -> ddr_web/1
  Black Box/11 -> ddr_dqs_o/1
  Black Box/12 -> ddr_dqs_t/1
  Black Box/13 -> ddr_csb/1
  Black Box/14 -> ddr_cke/1

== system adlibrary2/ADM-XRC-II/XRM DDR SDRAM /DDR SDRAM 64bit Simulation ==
  cache_data_in : Inport  Port=1  LatchInput=off
  cache_addr : Inport  Port=2  LatchInput=off
  cache_write : Inport  Port=3  LatchInput=off
  ddr_page : Inport  Port=4  LatchInput=off
  ddr_addr : Inport  Port=5  LatchInput=off
  ddr_read : Inport  Port=6  LatchInput=off
  ddr_write : Inport  Port=7  LatchInput=off
  Disregard Subsystem : xbsIndex_r3/Disregard Subsystem  Tag=discardX
  S-Function : S-Function  FunctionName=ddr64  Parameters=memsize,0
  Subsystem : Subsystem
  gi{0..6} (7 alike) : xbsIndex_r3/Gateway Out  output_type=Double  nbits=8  bin_pt=6  arith_type=Boolean  quantization=Truncate  overflow=Wrap  hdl_port=off  timing_constraint=None  locs_specified=off  LOCs={}  needs_fixed_name=off  show_param=off
  cache_data_out : Outport
  ddr_busy : Outport  Port=2
  ddr_status : Outport  Port=3
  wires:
  S-Function/1 -> Subsystem/1(In1)
  S-Function/2 -> Subsystem/2(In2)
  cache_data_in/1 -> gi0/1
  cache_addr/1 -> gi1/1
  cache_write/1 -> gi2/1
  ddr_page/1 -> gi3/1
  ddr_addr/1 -> gi4/1
  ddr_read/1 -> gi5/1
  ddr_write/1 -> gi6/1
  gi0/1 -> S-Function/1
  gi1/1 -> S-Function/2
  gi2/1 -> S-Function/3
  gi3/1 -> S-Function/4
  gi4/1 -> S-Function/5
  gi5/1 -> S-Function/6
  gi6/1 -> S-Function/7
  S-Function/3 -> Subsystem/3(In3)
  Subsystem/1(Out1) -> cache_data_out/1
  Subsystem/2(Out2) -> ddr_busy/1
  Subsystem/3(Out3) -> ddr_status/1

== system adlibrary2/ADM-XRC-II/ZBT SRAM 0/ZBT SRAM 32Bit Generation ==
  d : Inport  Port=1  LatchInput=off
  a : Inport  Port=2  LatchInput=off
  w : Inport  Port=3  LatchInput=off
  r : Inport  Port=4  LatchInput=off
  be : Inport  Port=5  LatchInput=off
  adlocb_in : Inport  Port=6  LatchInput=off
  Black Box : S-Function  FunctionName=xlblackbox2  Parameters=sfcn_mwsv__  mask(Xilinx Blackbox Block){init_code=zbt32_config, sim_method=Inactive, engine_block=, show_param=on, xl_area=[88, 129, 0, 35, 0, 0, 0], xl_use_area=on, adlocb_devid=0}
      mask prompts: init_code "Block Configuration M-Function"; sim_method "Simulation Mode"; engine_block "HDL Co-Simulator To Use  (specify helper block by name)"; show_param "---------------------- Show Implementation Parameters -----------------------------------------------------------------------------------"; xl_area "FPGA Area [Slices, FFs, BRAMs, LUTs, IOBs, Emb. Mults, TBUFs]"; xl_use_area "Use Area Above For Estimation"; adlocb_devid "ADLOCB DEV ID"
      mask help: Incorporates black box HDL and simulation model into a System Generator design. You must supply a Black Box with certain information about the HDL component you would like to bring into System Generator. This information is provided through a Matlab function. When "Simulation Mode" is set to "Inactive," you will typically want to provide a separate simulation model by using a Simulation Multiplexer. When "Simulation Mode" is set to "Use HDL Co-Simulation", you must include a ModelSim block in the design.
      mask init:
      | [designRoot, family, part, speed, package, simulinkPeriod, sysclkPeriod, dbl_ovrd, trimVbit] = xlSysgenSettings(gcb,0,0);
      | 
      | [bg,fg] = xlcmap('XBlock');
      | iPos = get_param(gcb,'Position');
      | iWidth=iPos(3)-iPos(1); iHeight=iPos(4)-iPos(2);
      | iCx=iWidth/2;
      | iCy=iHeight/2;
      | [logoX, logoY] = xlogo(iPos);
      | zstr='z'; zpstr='-1';
      | zstrx = iCx-3; if (zstrx<16) zstr='';zpstr=''; end
      | zstry = iCy;
      | 
      | precision0 = 1;
      | latency = 0;
      | dblOvrd = 0;
      | 
      | mdlPath = xlGetMdlDir(bdroot);
      | 
      | refBlk = get_param(gcb,'referenceBlock');
      | if (isempty(refBlk) | strncmp(refBlk,'xbsIndex',8))
      | 	srcPath = mdlPath;
      | else
      | 	srcPath = xlPathToReference;
      | 	if (isempty(srcPath))
      | 		srcPath = mdlPath;
      | 	end
      | end
      | 
      | if (sim_method==2)
      | 	validEngineBlock = 0;
      | 	try
      | 	  engineBlock = xlBlockNameRelPath(get_param(gcb,'Parent'),engine_block);
      | 	catch
      | 	  engineBlock = '//';
      | 	end
      | 	try 
      | 	  engineWorkDir = get_param(engineBlock,'dir');
      | 	  validEngineBlock = 1;
      | 	catch
      | 	end
      | end
      | 
      | % just pass everything to s-function
      | sfcn_mwsv__ = get_param(gcb, 'MaskWSVariables');
      | 
      | plabel = xlbbPortLabelStruct(gcb,init_code,mdlPath);
  Constant : Constant  Value=0
  Convert : xbsIndex_r3/Convert  arith_type=Unsigned  n_bits=34  bin_pt=0  quantization=Truncate  overflow=Wrap  latency=0  explicit_period=on  period=1  dbl_ovrd=off  show_param=off  inserted_by_tool=off  pipeline=off
  Terminator{,1..3} (4 alike) : Terminator
  ra0 : xbsIndex_r3/Gateway Out  output_type=Double  nbits=8  bin_pt=6  arith_type=Boolean  quantization=Truncate  overflow=Wrap  hdl_port=on  timing_constraint=None  locs_specified=off  LOCs={}  needs_fixed_name=off  show_param=off
  rc0 : xbsIndex_r3/Gateway Out  output_type=Double  nbits=8  bin_pt=6  arith_type=Boolean  quantization=Truncate  overflow=Wrap  hdl_port=on  timing_constraint=None  locs_specified=off  LOCs={}  needs_fixed_name=off  show_param=off
  rd0_i : xbsIndex_r3/Gateway In  arith_type=Unsigned  n_bits=32  bin_pt=0  quantization=Truncate  overflow=Wrap  period=1  timing_constraint=None  locs_specified=off  LOCs={}  needs_fixed_name=off  dbl_ovrd=off  show_param=off
  rd0_o : xbsIndex_r3/Gateway Out  output_type=Double  nbits=8  bin_pt=6  arith_type=Boolean  quantization=Truncate  overflow=Wrap  hdl_port=on  timing_constraint=None  locs_specified=off  LOCs={}  needs_fixed_name=off  show_param=off
  rd0_t : xbsIndex_r3/Gateway Out  output_type=Double  nbits=8  bin_pt=6  arith_type=Boolean  quantization=Truncate  overflow=Wrap  hdl_port=on  timing_constraint=None  locs_specified=off  LOCs={}  needs_fixed_name=off  show_param=off
  q : Outport
  qv : Outport  Port=2
  adlocb_out : Outport  Port=3
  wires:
  Black Box/6 -> rc0/1
  Black Box/5 -> ra0/1
  Black Box/4 -> rd0_t/1
  Black Box/3 -> rd0_o/1
  r/1 -> Black Box/4
  w/1 -> Black Box/3
  a/1 -> Black Box/2
  rc0/1 -> Terminator3/1
  ra0/1 -> Terminator2/1
  rd0_t/1 -> Terminator1/1
  rd0_o/1 -> Terminator/1
  Constant/1 -> rd0_i/1
  Black Box/2 -> qv/1
  Black Box/1 -> q/1
  d/1 -> Black Box/1
  rd0_i/1 -> Black Box/6
  be/1 -> Black Box/5
  adlocb_in/1 -> Black Box/7
  Black Box/7 -> Convert/1
  Convert/1 -> adlocb_out/1

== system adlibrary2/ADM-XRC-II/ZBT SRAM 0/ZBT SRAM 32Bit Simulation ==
  d : Inport  Port=1  LatchInput=off
  a : Inport  Port=2  LatchInput=off
  w : Inport  Port=3  LatchInput=off
  r : Inport  Port=4  LatchInput=off
  be : Inport  Port=5  LatchInput=off
  Disregard Subsystem : xbsIndex_r3/Disregard Subsystem  Tag=discardX
  Gateway In6 : xbsIndex_r3/Gateway In  arith_type=Boolean  n_bits=1  bin_pt=0  quantization=Truncate  overflow=Wrap  period=1  timing_constraint=None  locs_specified=off  LOCs={}  needs_fixed_name=off  dbl_ovrd=on  show_param=off
  Gateway In7 : xbsIndex_r3/Gateway In  arith_type=Unsigned  n_bits=32  bin_pt=0  quantization=Truncate  overflow=Wrap  period=1  timing_constraint=None  locs_specified=off  LOCs={}  needs_fixed_name=off  dbl_ovrd=on  show_param=off
  Gateway Out{,1..4} (5 alike) : xbsIndex_r3/Gateway Out  output_type=Double  nbits=8  bin_pt=6  arith_type=Boolean  quantization=Truncate  overflow=Wrap  hdl_port=off  timing_constraint=None  locs_specified=off  LOCs={}  needs_fixed_name=off  show_param=off
  S-Function : S-Function  FunctionName=zbt32  Parameters=0
  q : Outport
  qv : Outport  Port=2
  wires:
  S-Function/2 -> Gateway In6/1
  Gateway In7/1 -> q/1
  Gateway In6/1 -> qv/1
  Gateway Out3/1 -> S-Function/4
  Gateway Out2/1 -> S-Function/3
  Gateway Out1/1 -> S-Function/2
  Gateway Out/1 -> S-Function/1
  S-Function/1 -> Gateway In7/1
  r/1 -> Gateway Out3/1
  w/1 -> Gateway Out2/1
  a/1 -> Gateway Out1/1
  d/1 -> Gateway Out/1
  Gateway Out4/1 -> S-Function/5
  be/1 -> Gateway Out4/1

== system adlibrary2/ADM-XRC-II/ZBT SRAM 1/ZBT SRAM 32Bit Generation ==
  d : Inport  Port=1  LatchInput=off
  a : Inport  Port=2  LatchInput=off
  w : Inport  Port=3  LatchInput=off
  r : Inport  Port=4  LatchInput=off
  be : Inport  Port=5  LatchInput=off
  adlocb_in : Inport  Port=6  LatchInput=off
  Black Box : S-Function  FunctionName=xlblackbox2  Parameters=sfcn_mwsv__  mask(Xilinx Blackbox Block){init_code=zbt32_config, sim_method=Inactive, engine_block=, show_param=on, xl_area=[88, 129, 0, 35, 0, 0, 0], xl_use_area=on, adlocb_devid=1}
      mask prompts: init_code "Block Configuration M-Function"; sim_method "Simulation Mode"; engine_block "HDL Co-Simulator To Use  (specify helper block by name)"; show_param "---------------------- Show Implementation Parameters -----------------------------------------------------------------------------------"; xl_area "FPGA Area [Slices, FFs, BRAMs, LUTs, IOBs, Emb. Mults, TBUFs]"; xl_use_area "Use Area Above For Estimation"; adlocb_devid "ADLOCB DEV ID"
      mask help: Incorporates black box HDL and simulation model into a System Generator design. You must supply a Black Box with certain information about the HDL component you would like to bring into System Generator. This information is provided through a Matlab function. When "Simulation Mode" is set to "Inactive," you will typically want to provide a separate simulation model by using a Simulation Multiplexer. When "Simulation Mode" is set to "Use HDL Co-Simulation", you must include a ModelSim block in the design.
      mask init:
      | [designRoot, family, part, speed, package, simulinkPeriod, sysclkPeriod, dbl_ovrd, trimVbit] = xlSysgenSettings(gcb,0,0);
      | 
      | [bg,fg] = xlcmap('XBlock');
      | iPos = get_param(gcb,'Position');
      | iWidth=iPos(3)-iPos(1); iHeight=iPos(4)-iPos(2);
      | iCx=iWidth/2;
      | iCy=iHeight/2;
      | [logoX, logoY] = xlogo(iPos);
      | zstr='z'; zpstr='-1';
      | zstrx = iCx-3; if (zstrx<16) zstr='';zpstr=''; end
      | zstry = iCy;
      | 
      | precision0 = 1;
      | latency = 0;
      | dblOvrd = 0;
      | 
      | mdlPath = xlGetMdlDir(bdroot);
      | 
      | refBlk = get_param(gcb,'referenceBlock');
      | if (isempty(refBlk) | strncmp(refBlk,'xbsIndex',8))
      | 	srcPath = mdlPath;
      | else
      | 	srcPath = xlPathToReference;
      | 	if (isempty(srcPath))
      | 		srcPath = mdlPath;
      | 	end
      | end
      | 
      | if (sim_method==2)
      | 	validEngineBlock = 0;
      | 	try
      | 	  engineBlock = xlBlockNameRelPath(get_param(gcb,'Parent'),engine_block);
      | 	catch
      | 	  engineBlock = '//';
      | 	end
      | 	try 
      | 	  engineWorkDir = get_param(engineBlock,'dir');
      | 	  validEngineBlock = 1;
      | 	catch
      | 	end
      | end
      | 
      | % just pass everything to s-function
      | sfcn_mwsv__ = get_param(gcb, 'MaskWSVariables');
      | adlocb_devid = 1;
      | plabel = xlbbPortLabelStruct(gcb,init_code,mdlPath);
  Constant : Constant  Value=0
  Terminator{,1..3} (4 alike) : Terminator
  ra1 : xbsIndex_r3/Gateway Out  output_type=Double  nbits=8  bin_pt=6  arith_type=Boolean  quantization=Truncate  overflow=Wrap  hdl_port=on  timing_constraint=None  locs_specified=off  LOCs={}  needs_fixed_name=off  show_param=off
  rc1 : xbsIndex_r3/Gateway Out  output_type=Double  nbits=8  bin_pt=6  arith_type=Boolean  quantization=Truncate  overflow=Wrap  hdl_port=on  timing_constraint=None  locs_specified=off  LOCs={}  needs_fixed_name=off  show_param=off
  rd1_i : xbsIndex_r3/Gateway In  arith_type=Unsigned  n_bits=32  bin_pt=0  quantization=Truncate  overflow=Wrap  period=1  timing_constraint=None  locs_specified=off  LOCs={}  needs_fixed_name=off  dbl_ovrd=off  show_param=off
  rd1_o : xbsIndex_r3/Gateway Out  output_type=Double  nbits=8  bin_pt=6  arith_type=Boolean  quantization=Truncate  overflow=Wrap  hdl_port=on  timing_constraint=None  locs_specified=off  LOCs={}  needs_fixed_name=off  show_param=off
  rd1_t : xbsIndex_r3/Gateway Out  output_type=Double  nbits=8  bin_pt=6  arith_type=Boolean  quantization=Truncate  overflow=Wrap  hdl_port=on  timing_constraint=None  locs_specified=off  LOCs={}  needs_fixed_name=off  show_param=off
  q : Outport
  qv : Outport  Port=2
  adlocb_out : Outport  Port=3
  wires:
  Black Box/7 -> adlocb_out/1
  adlocb_in/1 -> Black Box/7
  be/1 -> Black Box/5
  rd1_i/1 -> Black Box/6
  d/1 -> Black Box/1
  Black Box/1 -> q/1
  Black Box/2 -> qv/1
  Constant/1 -> rd1_i/1
  rd1_o/1 -> Terminator/1
  rd1_t/1 -> Terminator1/1
  ra1/1 -> Terminator2/1
  rc1/1 -> Terminator3/1
  a/1 -> Black Box/2
  w/1 -> Black Box/3
  r/1 -> Black Box/4
  Black Box/3 -> rd1_o/1
  Black Box/4 -> rd1_t/1
  Black Box/5 -> ra1/1
  Black Box/6 -> rc1/1

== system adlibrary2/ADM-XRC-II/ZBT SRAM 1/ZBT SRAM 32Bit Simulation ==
  d : Inport  Port=1  LatchInput=off
  a : Inport  Port=2  LatchInput=off
  w : Inport  Port=3  LatchInput=off
  r : Inport  Port=4  LatchInput=off
  be : Inport  Port=5  LatchInput=off
  Disregard Subsystem : xbsIndex_r3/Disregard Subsystem  Tag=discardX
  Gateway In6 : xbsIndex_r3/Gateway In  arith_type=Boolean  n_bits=1  bin_pt=0  quantization=Truncate  overflow=Wrap  period=1  timing_constraint=None  locs_specified=off  LOCs={}  needs_fixed_name=off  dbl_ovrd=on  show_param=off
  Gateway In7 : xbsIndex_r3/Gateway In  arith_type=Unsigned  n_bits=32  bin_pt=0  quantization=Truncate  overflow=Wrap  period=1  timing_constraint=None  locs_specified=off  LOCs={}  needs_fixed_name=off  dbl_ovrd=on  show_param=off
  Gateway Out{,1..4} (5 alike) : xbsIndex_r3/Gateway Out  output_type=Double  nbits=8  bin_pt=6  arith_type=Boolean  quantization=Truncate  overflow=Wrap  hdl_port=off  timing_constraint=None  locs_specified=off  LOCs={}  needs_fixed_name=off  show_param=off
  S-Function : S-Function  FunctionName=zbt32  Parameters=1
  q : Outport
  qv : Outport  Port=2
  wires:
  be/1 -> Gateway Out4/1
  Gateway Out4/1 -> S-Function/5
  d/1 -> Gateway Out/1
  a/1 -> Gateway Out1/1
  w/1 -> Gateway Out2/1
  r/1 -> Gateway Out3/1
  S-Function/1 -> Gateway In7/1
  Gateway Out/1 -> S-Function/1
  Gateway Out1/1 -> S-Function/2
  Gateway Out2/1 -> S-Function/3
  Gateway Out3/1 -> S-Function/4
  Gateway In6/1 -> qv/1
  Gateway In7/1 -> q/1
  S-Function/2 -> Gateway In6/1

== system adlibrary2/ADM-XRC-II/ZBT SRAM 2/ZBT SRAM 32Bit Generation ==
  d : Inport  Port=1  LatchInput=off
  a : Inport  Port=2  LatchInput=off
  w : Inport  Port=3  LatchInput=off
  r : Inport  Port=4  LatchInput=off
  be : Inport  Port=5  LatchInput=off
  adlocb_in : Inport  Port=6  LatchInput=off
  Black Box : S-Function  FunctionName=xlblackbox2  Parameters=sfcn_mwsv__  mask(Xilinx Blackbox Block){init_code=zbt32_config, sim_method=Inactive, engine_block=, show_param=on, xl_area=[88, 129, 0, 35, 0, 0, 0], xl_use_area=on, adlocb_devid=2}
      mask prompts: init_code "Block Configuration M-Function"; sim_method "Simulation Mode"; engine_block "HDL Co-Simulator To Use  (specify helper block by name)"; show_param "---------------------- Show Implementation Parameters -----------------------------------------------------------------------------------"; xl_area "FPGA Area [Slices, FFs, BRAMs, LUTs, IOBs, Emb. Mults, TBUFs]"; xl_use_area "Use Area Above For Estimation"; adlocb_devid "ADLOCB DEV ID"
      mask help: Incorporates black box HDL and simulation model into a System Generator design. You must supply a Black Box with certain information about the HDL component you would like to bring into System Generator. This information is provided through a Matlab function. When "Simulation Mode" is set to "Inactive," you will typically want to provide a separate simulation model by using a Simulation Multiplexer. When "Simulation Mode" is set to "Use HDL Co-Simulation", you must include a ModelSim block in the design.
      mask init:
      | [designRoot, family, part, speed, package, simulinkPeriod, sysclkPeriod, dbl_ovrd, trimVbit] = xlSysgenSettings(gcb,0,0);
      | 
      | [bg,fg] = xlcmap('XBlock');
      | iPos = get_param(gcb,'Position');
      | iWidth=iPos(3)-iPos(1); iHeight=iPos(4)-iPos(2);
      | iCx=iWidth/2;
      | iCy=iHeight/2;
      | [logoX, logoY] = xlogo(iPos);
      | zstr='z'; zpstr='-1';
      | zstrx = iCx-3; if (zstrx<16) zstr='';zpstr=''; end
      | zstry = iCy;
      | 
      | precision0 = 1;
      | latency = 0;
      | dblOvrd = 0;
      | 
      | mdlPath = xlGetMdlDir(bdroot);
      | 
      | refBlk = get_param(gcb,'referenceBlock');
      | if (isempty(refBlk) | strncmp(refBlk,'xbsIndex',8))
      | 	srcPath = mdlPath;
      | else
      | 	srcPath = xlPathToReference;
      | 	if (isempty(srcPath))
      | 		srcPath = mdlPath;
      | 	end
      | end
      | 
      | if (sim_method==2)
      | 	validEngineBlock = 0;
      | 	try
      | 	  engineBlock = xlBlockNameRelPath(get_param(gcb,'Parent'),engine_block);
      | 	catch
      | 	  engineBlock = '//';
      | 	end
      | 	try 
      | 	  engineWorkDir = get_param(engineBlock,'dir');
      | 	  validEngineBlock = 1;
      | 	catch
      | 	end
      | end
      | 
      | % just pass everything to s-function
      | sfcn_mwsv__ = get_param(gcb, 'MaskWSVariables');
      | 
      | plabel = xlbbPortLabelStruct(gcb,init_code,mdlPath);
  Constant : Constant  Value=0
  Terminator{,1..3} (4 alike) : Terminator
  ra2 : xbsIndex_r3/Gateway Out  output_type=Double  nbits=8  bin_pt=6  arith_type=Boolean  quantization=Truncate  overflow=Wrap  hdl_port=on  timing_constraint=None  locs_specified=off  LOCs={}  needs_fixed_name=off  show_param=off
  rc2 : xbsIndex_r3/Gateway Out  output_type=Double  nbits=8  bin_pt=6  arith_type=Boolean  quantization=Truncate  overflow=Wrap  hdl_port=on  timing_constraint=None  locs_specified=off  LOCs={}  needs_fixed_name=off  show_param=off
  rd2_i : xbsIndex_r3/Gateway In  arith_type=Unsigned  n_bits=32  bin_pt=0  quantization=Truncate  overflow=Wrap  period=1  timing_constraint=None  locs_specified=off  LOCs={}  needs_fixed_name=off  dbl_ovrd=off  show_param=off
  rd2_o : xbsIndex_r3/Gateway Out  output_type=Double  nbits=8  bin_pt=6  arith_type=Boolean  quantization=Truncate  overflow=Wrap  hdl_port=on  timing_constraint=None  locs_specified=off  LOCs={}  needs_fixed_name=off  show_param=off
  rd2_t : xbsIndex_r3/Gateway Out  output_type=Double  nbits=8  bin_pt=6  arith_type=Boolean  quantization=Truncate  overflow=Wrap  hdl_port=on  timing_constraint=None  locs_specified=off  LOCs={}  needs_fixed_name=off  show_param=off
  q : Outport
  qv : Outport  Port=2
  adlocb_out : Outport  Port=3
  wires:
  Black Box/7 -> adlocb_out/1
  adlocb_in/1 -> Black Box/7
  be/1 -> Black Box/5
  rd2_i/1 -> Black Box/6
  d/1 -> Black Box/1
  Black Box/1 -> q/1
  Black Box/2 -> qv/1
  Constant/1 -> rd2_i/1
  rd2_o/1 -> Terminator/1
  rd2_t/1 -> Terminator1/1
  ra2/1 -> Terminator2/1
  rc2/1 -> Terminator3/1
  a/1 -> Black Box/2
  w/1 -> Black Box/3
  r/1 -> Black Box/4
  Black Box/3 -> rd2_o/1
  Black Box/4 -> rd2_t/1
  Black Box/5 -> ra2/1
  Black Box/6 -> rc2/1
